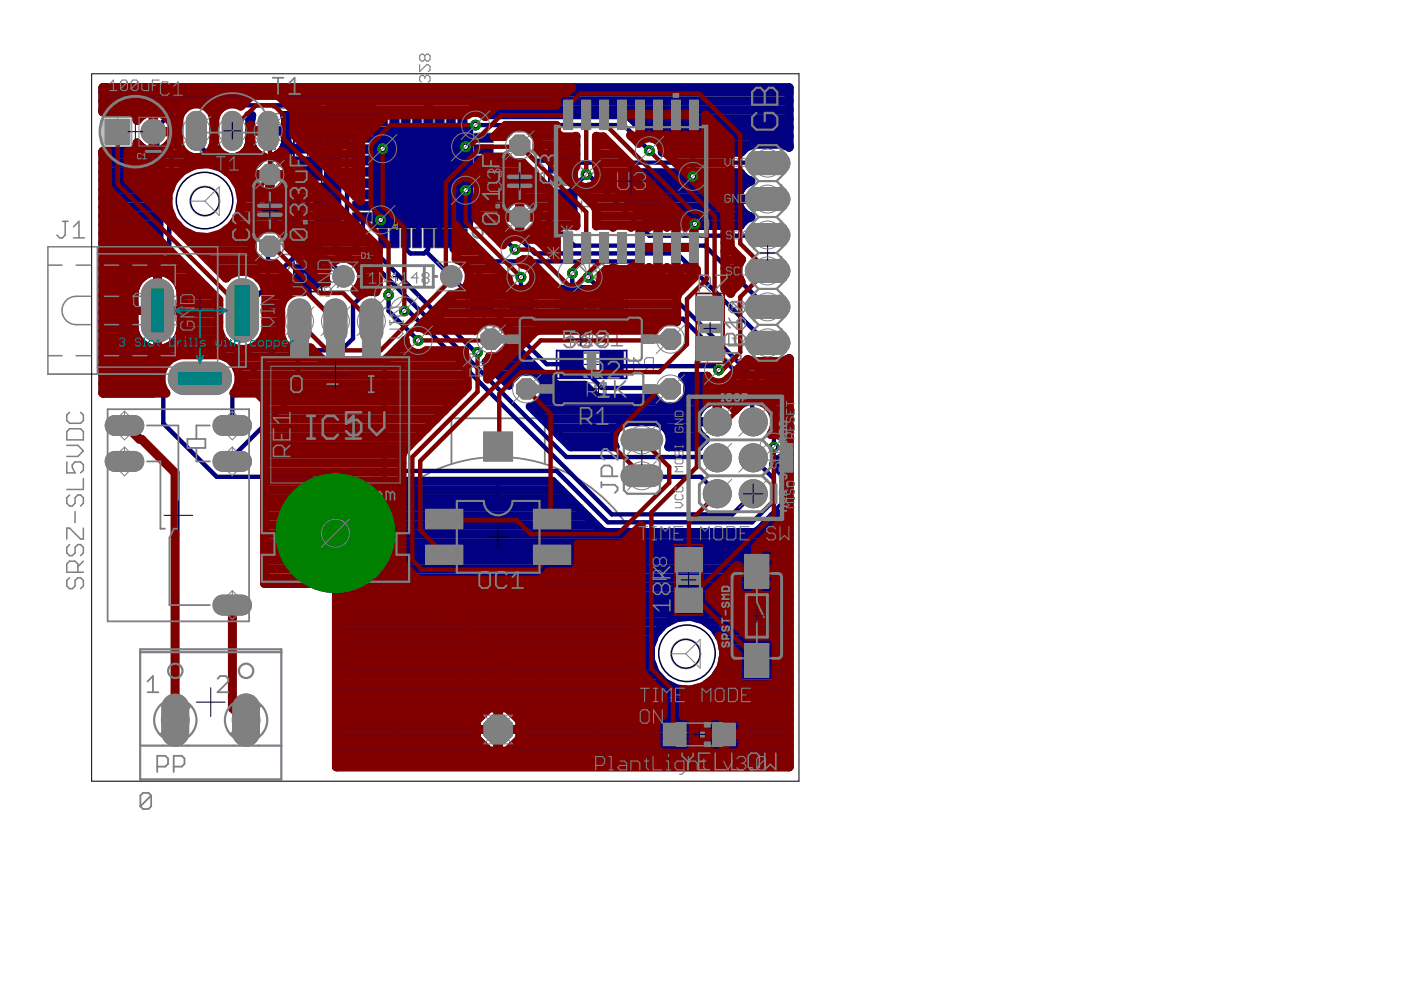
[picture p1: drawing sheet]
<svg xmlns="http://www.w3.org/2000/svg" width="297mm" height="210mm" viewBox="0 0 297 210" stroke-linecap="round" stroke-linejoin="round" font-family="sans-serif">
<g fill="none" stroke="#000" stroke-width=".21">
<path d="M63.4 31.5h3.7M65.2 29.7v3.6M86.6 37.6h6.1M89.6 34.6v6.1M117.8 38.4h3.1M119.3 36.9v3M63.4 54.4h3.7M65.2 52.6v3.6M104.8 63.5h3.1M106.4 62v3.1M123.9 77.3h3.1M123.9 63.5h3.1"/>
<path d="M125.4 62v3.1M125.4 75.7v3.1M102.6 136.7h6.1M105.6 133.6v6.1"/>
</g>
<g fill="none" stroke="#808080" stroke-width=".32">
<path d="M57.8 27.6v2.3M57.8 31.1h.6v.6h-.6zM57.8 28.8h3.5l-1.2 1.1M59.5 21.8v1.1M60.1 24.1h-2.3v1.7l.6 .6h1.7M60.7 32.9l.6 .5v1.2l-.6 .6h-2.3M60.7 32.9h-2.3l-.6 .5v1.2l.6 .6M60.7 32.9l-2.3 2.3M61.3 20.6v2.3h-3.5M62.9 28.7v5.7M67.6 28.7v5.7M69.8 32.9l-.6 .5v1.2l.6 .6h2.3l.6-.6v-1.2l-.6-.5"/>
<path d="M71 29.4v2.3l1.7-1.8h-3.5M111.9 39.1l1.1 1.2M115.4 35.6v2.4h-1.8l.6-1.2v-.6l-.6-.6h-1.1l-.6 .6v1.2l.6 .6M123.3 38h3.5M123.3 35.6l1.8 1.8M125.1 39.7l-.6-.6h-.6l-.6 .6v1.2l.6 .5h.6l.6-.5M125.1 39.7l.5-.6h.6l.6 .6v1.2l-.6 .5h-.6l-.5-.5M125.1 39.7v1.2M126.8 35.6l-2.3 2.4M58.4 55.1l-.6 .6v1.2l.6 .5h2.3l.6-.5v-1.2l-.6-.6M61.3 51.6v2.4h-1.8l.6-1.2v-.6l-.6-.6h-1.1l-.6 .6v1.2l.6 .6M62.9 51.5v5.8"/>
<path d="M67.6 51.5v5.8M69.2 58.6v2.4M69.2 59.8h3.5l-1.2 1.2M71 52.8v1.2M71.5 55.1h-2.3v1.8l.6 .5h1.7M72.7 51.6v2.4h-3.5M104.2 58.4l.6-.6h1.7v1.2l-.6 .6h-1.1l-.6-.6zM104.2 56.1l1.2 .6 1.1 1.1M108.9 58.4l-1.2 1.2M110 58.4h-1.7l-.6-.6v-1.1l.6-.6h1.7v3.5M111.9 41.4h3.5v-1.7l-.6-.6h-1.2l-.6 .6v1.7M122.6 56.1l2.4 2.3"/>
<path d="M123.3 43.8h3.5l-1.2 1.2M123.3 42.6v2.4M124.4 57.8l-1.8 1.8M125 56.1v3.5M126.7 57.8l-.6-.6v-.5l.6-.6h1.2l.6 .6v.5l-.6 .6M126.7 57.8l-.6 .6v.6l.6 .6h1.2l.6-.6v-.6l-.6-.6M126.7 57.8h1.2M129.6 59.6h2.4M132 57.2l-1.2-1.1v3.5M69.2 62.1h.6v.6h-.6zM72.1 63.9l.6 .6v1.1l-.6 .6h-2.3M72.1 63.9h-2.3l-.6 .6v1.1l.6 .6"/>
<path d="M72.1 63.9l-2.3 2.3M100.7 67.5l2.3 2.3M102.4 69.3l-1.7 1.7M103 67.5v3.5M104.8 69.3l-.6 .5v.6l.6 .6h1.1l.6-.6v-.6l-.6-.5M104.8 69.3l-.6-.6v-.6l.6-.6h1.1l.6 .6v.6l-.6 .6M104.8 69.3h1.1M107.7 71h2.3M110 68.7l-1.1-1.2v3.5M122.6 69.8l2.4 2.3M122.6 69.8v.6l.6 .6h1.2l.6-.6M123.2 69.3h.6"/>
<path d="M123.2 69.3l-.6 .5M124.4 71.5l-1.8 1.8M125 69.8v3.5M125 68.1l-.6-.6h-1.2l-.6 .6v.6l.6 .6M126.7 71.5l-.6 .6v.6l.6 .6h1.2l.6-.6v-.6l-.6-.6M126.7 69.8h1.8M126.7 69.8l-.6 .6v.6l.6 .5M126.7 69.8l-.6-.5v-1.2l.6-.6h1.8v3.5M126.7 71.5h1.2M127.3 69.8l-1.2 1.2M127.9 69.8l.6 .6M128.5 71l-.6 .5"/>
<path d="M129.6 73.3h2.4M132 71l-1.2-1.2v3.5M122.6 83h2.4l-1.8-1.8v3.5M127.3 83.5l-1.2 1.2M128.5 83.5h-1.8l-.6-.5v-1.2l.6-.6h1.8v3.5"/>
</g>
<g fill="none" stroke="#808080" stroke-width=".23">
<path d="M89 13.7v1.5l1.4-1.5h.4l.4 .4v.7l-.4 .4M90.1 11.9v.7M90.1 16.3v.4M90.1 11.9l.3-.4h.4l.4 .4v.7l-.4 .4h-.4l-.3-.4M90.1 16.3l.3-.3h.4l.4 .3v.8l-.4 .3M90.1 11.9l-.4-.4h-.4l-.3 .4v.7l.3 .4h.4l.4-.4M90.1 16.3l-.4-.3h-.4l-.3 .3v.8l.3 .3M91.2 18.2l-2.2 1.5M89 23.1l.3-.4h.4l.4 .4v1.1h-.8l-.3-.4zM89 36.2v1.5h2.2v-1.5M89 38.4h2.2l-.8 .8 .8 .7h-2.2M89 25v1.4"/>
<path d="M89 31.7h1.4l.8 .7-.8 .7h-1.4M89 25.7h2.2l-.8 .7M90.1 20.8v.8M90.1 29.8v.7M90.1 31.7v1.4M90.1 36.9v.8M90.1 20.8l.3-.3h.4l.4 .3v.8l-.4 .3h-.4l-.3-.3M90.1 29.8l.3-.4h.4l.4 .4v.7l-.4 .4h-.4l-.3-.4M90.1 20.8l-.4-.3h-.4l-.3 .3v.8l.3 .3h.4l.4-.3M90.1 29.8l-.4-.4h-.4l-.3 .4v.7l.3 .4h.4l.4-.4M90.8 33.9l.4 .4v.7l-.4 .4h-1.5l-.3-.4v-.7l.3-.4h.8v.8M91.2 27.2l-2.2 1.5"/>
<path d="M91.2 22.7l-.4 .7-.7 .8M89 42.9h1.4l.8 .7-.8 .8h-1.4M89 41.4h2.2M90.1 42.9v1.5M91.2 40.7v1.4M106.1 40.3v1.5l1.1-1.2h-2.2M107.2 42.5h-1.9l-.3 .4v.7l.3 .4h1.9"/>
</g>
<path d="M116.9 35.5v5.8M121.8 35.5v5.8M103.5 61.1h5.8M103.5 66h5.8M122.5 74.8h5.8M122.5 79.7h5.8M122.5 61.1h5.8M122.5 66h5.8" fill="none" stroke="#808080" stroke-width=".47"/>
<g fill="#808080" stroke="#808080" stroke-width=".21">
<path d="M120.4 74.6h2.2v5.3h-2.2z"/>
<path d="M128.3 74.6h2.2v5.3h-2.2z"/>
<path d="M116.7 33.3h5.3v2.2h-5.3z"/>
<path d="M116.7 41.3h5.3v2.2h-5.3z"/>
<path d="M120.4 60.9h2.2v5.3h-2.2z"/>
<path d="M128.3 60.9h2.2v5.3h-2.2z"/>
<path d="M109.2 60.9h2.2v5.3h-2.2z"/>
<path d="M101.3 60.9h2.2v5.3h-2.2z"/>
<path d="M97.3 48.3h1.4v3h-1.4z"/>
<path d="M94.9 48.3h1.4v3h-1.4z"/>
<path d="M92.5 48.3h1.4v3h-1.4z"/>
<path d="M90.1 48.3h1.4v3h-1.4z"/>
<path d="M87.7 48.3h1.4v3h-1.4z"/>
<path d="M85.3 48.3h1.4v3h-1.4z"/>
<path d="M83 48.3h1.3v3h-1.3z"/>
<path d="M80.5 48.3h1.4v3h-1.4z"/>
<path d="M76 45.4h3v1.3h-3z"/>
<path d="M76 43h3v1.3h-3z"/>
<path d="M76 40.6h3v1.3h-3z"/>
<path d="M76 38.2h3v1.3h-3z"/>
<path d="M76 35.8h3v1.3h-3z"/>
<path d="M76 33.4h3v1.3h-3z"/>
<path d="M76 31h3v1.3h-3z"/>
<path d="M76 28.6h3v1.3h-3z"/>
<path d="M80.5 24h1.4v3h-1.4z"/>
<path d="M83 24h1.3v3h-1.3z"/>
<path d="M85.3 24h1.4v3h-1.4z"/>
<path d="M87.7 24h1.4v3h-1.4z"/>
<path d="M90.1 24h1.4v3h-1.4z"/>
<path d="M92.5 24h1.4v3h-1.4z"/>
<path d="M94.9 24h1.4v3h-1.4z"/>
<path d="M97.3 24h1.4v3h-1.4z"/>
<path d="M100.3 28.6h3v1.3h-3z"/>
<path d="M100.3 31h3v1.3h-3z"/>
<path d="M100.3 33.4h3v1.3h-3z"/>
<path d="M100.3 35.8h3v1.3h-3z"/>
<path d="M100.3 38.2h3v1.3h-3z"/>
<path d="M100.3 40.6h3v1.3h-3z"/>
<path d="M100.3 43h3v1.3h-3z"/>
<path d="M100.3 45.4h3v1.3h-3z"/>
<path d="M62.7 34.4h5.1v2.2h-5.1z"/>
<path d="M62.7 26.4h5.1v2.3h-5.1z"/>
<path d="M62.7 49.3h5.1v2.2h-5.1z"/>
<path d="M62.7 57.3h5.1v2.2h-5.1z"/>
<path d="M124.5 75.2h1.8v4.2h-1.8z"/>
<path d="M117.2 37.5h4.2v1.8h-4.2z"/>
<path d="M124.5 61.4h1.8v4.2h-1.8z"/>
<path d="M105.5 61.4h1.8v4.2h-1.8z"/>
<path d="M64 30.9h2.4v1.2h-2.4z"/>
<path d="M64 53.8h2.4v1.2h-2.4z"/>
<path d="M127.3 74.5h4.8v5.5h-4.8z"/>
<path d="M118.8 74.5h4.7v5.5h-4.7z"/>
<path d="M116.6 40.3h5.4v4.8h-5.4z"/>
<path d="M116.6 31.7h5.4v4.8h-5.4z"/>
<path d="M127.3 60.8h4.8v5.5h-4.8z"/>
<path d="M118.8 60.8h4.7v5.5h-4.7z"/>
<path d="M99.7 60.8h4.8v5.5h-4.8z"/>
<path d="M108.2 60.8h4.8v5.5h-4.8z"/>
<path d="M97.2 48.6h1.7v3.8h-1.7z"/>
<path d="M94.8 48.6h1.7v3.8h-1.7z"/>
<path d="M92.4 48.6h1.7v3.8h-1.7z"/>
<path d="M90 48.6h1.7v3.8h-1.7z"/>
<path d="M87.6 48.6h1.7v3.8h-1.7z"/>
<path d="M85.2 48.6h1.7v3.8h-1.7z"/>
<path d="M82.8 48.6h1.7v3.8h-1.7z"/>
<path d="M80.4 48.6h1.7v3.8h-1.7z"/>
<path d="M74.8 45.2h3.9v1.7h-3.9z"/>
<path d="M74.8 42.8h3.9v1.7h-3.9z"/>
<path d="M74.8 40.4h3.9v1.7h-3.9z"/>
<path d="M74.8 38h3.9v1.7h-3.9z"/>
<path d="M74.8 35.6h3.9v1.7h-3.9z"/>
<path d="M74.8 33.2h3.9v1.7h-3.9z"/>
<path d="M74.8 30.8h3.9v1.7h-3.9z"/>
<path d="M74.8 28.4h3.9v1.7h-3.9z"/>
<path d="M80.4 22.9h1.7v3.8h-1.7z"/>
<path d="M82.8 22.9h1.7v3.8h-1.7z"/>
<path d="M85.2 22.9h1.7v3.8h-1.7z"/>
<path d="M87.6 22.9h1.7v3.8h-1.7z"/>
<path d="M90 22.9h1.7v3.8h-1.7z"/>
<path d="M92.4 22.9h1.7v3.8h-1.7z"/>
<path d="M94.8 22.9h1.7v3.8h-1.7z"/>
<path d="M97.2 22.9h1.7v3.8h-1.7z"/>
<path d="M100.6 28.4h3.8v1.7h-3.8z"/>
<path d="M100.6 30.8h3.8v1.7h-3.8z"/>
<path d="M100.6 33.2h3.8v1.7h-3.8z"/>
<path d="M100.6 35.6h3.8v1.7h-3.8z"/>
<path d="M100.6 38h3.8v1.7h-3.8z"/>
<path d="M100.6 40.4h3.8v1.7h-3.8z"/>
<path d="M100.6 42.8h3.8v1.7h-3.8z"/>
<path d="M100.6 45.2h3.8v1.7h-3.8z"/>
<path d="M62.5 33.4h5.4v4.7h-5.4z"/>
<path d="M62.5 25h5.4v4.7h-5.4z"/>
<path d="M62.5 47.8h5.4v4.8h-5.4z"/>
<path d="M62.5 56.2h5.4v4.8h-5.4z"/>
<path d="M35 148.1a2.84 2.84 0 0 1 3-.8 2.84 2.84 0 0 1 2 2.5v5.8a2.85 2.85 0 0 1-2.8 2.6 2.85 2.85 0 0 1-2.9-2.6v-5.8l.2-.9z"/>
<path d="M50 148.1a2.84 2.84 0 0 1 3.1-.8 2.84 2.84 0 0 1 1.9 2.5v5.8a2.85 2.85 0 0 1-2.8 2.6 2.85 2.85 0 0 1-2.9-2.6v-5.8l.3-.9z"/>
<path d="M22.8 88.9a2.14 2.14 0 0 1 1.4-.8h4.4a2.13 2.13 0 0 1 1.9 2.1 2.13 2.13 0 0 1-1.9 2.1h-4.4a2.13 2.13 0 0 1-1.4-3.4z"/>
<path d="M22.8 96.5a2.14 2.14 0 0 1 1.4-.8h4.4a2.13 2.13 0 0 1 1.9 2.1 2.13 2.13 0 0 1-1.9 2.1h-4.4a2.13 2.13 0 0 1-1.4-3.4z"/>
<path d="M45.6 126.9a2.14 2.14 0 0 1 1.5-.7h4.3a2.13 2.13 0 0 1 1.9 2.1 2.13 2.13 0 0 1-1.9 2.1h-4.3a2.13 2.13 0 0 1-1.5-3.5z"/>
<path d="M45.6 88.9a2.14 2.14 0 0 1 1.5-.8h4.3a2.13 2.13 0 0 1 1.9 2.1 2.13 2.13 0 0 1-1.9 2.1h-4.3a2.13 2.13 0 0 1-1.5-3.4z"/>
<path d="M45.6 96.5a2.14 2.14 0 0 1 1.5-.8h4.3a2.13 2.13 0 0 1 1.9 2.1 2.13 2.13 0 0 1-1.9 2.1h-4.3a2.13 2.13 0 0 1-1.5-3.4z"/>
<path d="M76.9 64.2a2.45 2.45 0 0 1 2.6-.7 2.45 2.45 0 0 1 1.7 2.1v5a2.44 2.44 0 0 1-2.5 2.2 2.44 2.44 0 0 1-2.4-2.2v-5l.2-.7z"/>
<path d="M69.3 64.2a2.45 2.45 0 0 1 2.6-.7 2.45 2.45 0 0 1 1.7 2.1v5a2.44 2.44 0 0 1-2.5 2.2 2.44 2.44 0 0 1-2.4-2.2v-5l.2-.7z"/>
<path d="M61.6 64.2a2.45 2.45 0 0 1 2.7-.7 2.45 2.45 0 0 1 1.6 2.1v5a2.44 2.44 0 0 1-2.4 2.2 2.44 2.44 0 0 1-2.4-2.2v-5l.1-.7z"/>
<path d="M22.3 25.3h5.2v5.2h-5.2z"/>
<path d="M158.6 71.1l.9-.7 .8-.1h4.9a2.44 2.44 0 0 1 2.3 2.4 2.44 2.44 0 0 1-2.3 2.4h-4.9a2.44 2.44 0 0 1-2.1-1.5 2.44 2.44 0 0 1 .4-2.5z"/>
<path d="M158.6 63.5l.9-.7 .8-.2h4.9a2.44 2.44 0 0 1 2.3 2.5 2.44 2.44 0 0 1-2.3 2.4h-4.9a2.44 2.44 0 0 1-2.1-1.5 2.44 2.44 0 0 1 .4-2.5z"/>
<path d="M158.6 55.9l.9-.7 .8-.2h4.9a2.44 2.44 0 0 1 2.3 2.4 2.44 2.44 0 0 1-2.3 2.5h-4.9a2.44 2.44 0 0 1-2.1-1.5 2.44 2.44 0 0 1 .4-2.5z"/>
<path d="M158.6 48.2l.9-.6 .8-.2h4.9a2.44 2.44 0 0 1 2.3 2.4 2.44 2.44 0 0 1-2.3 2.5h-4.9a2.44 2.44 0 0 1-2.1-1.5 2.44 2.44 0 0 1 .4-2.6z"/>
<path d="M158.6 40.6l.9-.7 .8-.1h4.9a2.44 2.44 0 0 1 2.3 2.4 2.44 2.44 0 0 1-2.3 2.4h-4.9a2.44 2.44 0 0 1-2.1-1.5 2.44 2.44 0 0 1 .4-2.5z"/>
<path d="M158.6 33l.9-.7 .8-.1h4.9a2.44 2.44 0 0 1 2.3 2.4 2.44 2.44 0 0 1-2.3 2.4h-4.9a2.44 2.44 0 0 1-2.1-1.5 2.44 2.44 0 0 1 .4-2.5z"/>
<path d="M127.1 74.4h5.1v5.7h-5.1z"/>
<path d="M118.6 74.4h5.1v5.7h-5.1z"/>
<path d="M116.5 40.1h5.7v5.1h-5.7z"/>
<path d="M116.5 31.6h5.7v5.1h-5.7z"/>
<path d="M102.6 91.6h6.1v6.1h-6.1z"/>
<path d="M127.1 60.7h5.1v5.7h-5.1z"/>
<path d="M118.6 60.7h5.1v5.7h-5.1z"/>
<path d="M99.5 60.7h5.2v5.7h-5.2z"/>
<path d="M108.1 60.7h5.1v5.7h-5.1z"/>
<path d="M97 48.5h2v4.1h-2z"/>
<path d="M94.6 48.5h2v4.1h-2z"/>
<path d="M92.2 48.5h2v4.1h-2z"/>
<path d="M89.8 48.5h2v4.1h-2z"/>
<path d="M87.4 48.5h2v4.1h-2z"/>
<path d="M85 48.5h2v4.1h-2z"/>
<path d="M82.6 48.5h2v4.1h-2z"/>
<path d="M80.2 48.5h2v4.1h-2z"/>
<path d="M74.7 45h4.1v2h-4.1z"/>
<path d="M74.7 42.7h4.1v1.9h-4.1z"/>
<path d="M74.7 40.2h4.1v2h-4.1z"/>
<path d="M74.7 37.8h4.1v2h-4.1z"/>
<path d="M74.7 35.5h4.1v1.9h-4.1z"/>
<path d="M74.7 33h4.1v2h-4.1z"/>
<path d="M74.7 30.6h4.1v2h-4.1z"/>
<path d="M74.7 28.2h4.1v2h-4.1z"/>
<path d="M80.2 22.7h2v4.1h-2z"/>
<path d="M82.6 22.7h2v4.1h-2z"/>
<path d="M85 22.7h2v4.1h-2z"/>
<path d="M87.4 22.7h2v4.1h-2z"/>
<path d="M89.8 22.7h2v4.1h-2z"/>
<path d="M92.2 22.7h2v4.1h-2z"/>
<path d="M94.6 22.7h2v4.1h-2z"/>
<path d="M97 22.7h2v4.1h-2z"/>
<path d="M100.4 28.2h4.1v2h-4.1z"/>
<path d="M100.4 30.6h4.1v2h-4.1z"/>
<path d="M100.4 33h4.1v2h-4.1z"/>
<path d="M100.4 35.5h4.1v1.9h-4.1z"/>
<path d="M100.4 37.8h4.1v2h-4.1z"/>
<path d="M100.4 40.2h4.1v2h-4.1z"/>
<path d="M100.4 42.7h4.1v1.9h-4.1z"/>
<path d="M100.4 45h4.1v2h-4.1z"/>
<path d="M62.4 33.2h5.7v5.1h-5.7z"/>
<path d="M62.4 24.8h5.7v5.1h-5.7z"/>
<path d="M62.4 47.6h5.7v5.2h-5.7z"/>
<path d="M62.4 56h5.7v5.2h-5.7z"/>
<path d="M40 24.4a2.14 2.14 0 0 1 2.3-.7 2.14 2.14 0 0 1 1.5 1.8v4.4a2.15 2.15 0 0 1-2.2 2 2.15 2.15 0 0 1-2.1-2v-4.4z"/>
<path d="M55.2 24.4a2.14 2.14 0 0 1 2.3-.7 2.14 2.14 0 0 1 1.5 1.8v4.4a2.15 2.15 0 0 1-2.1 2 2.15 2.15 0 0 1-2.2-2v-4.4z"/>
<path d="M47.6 24.4a2.14 2.14 0 0 1 2.3-.7 2.14 2.14 0 0 1 1.5 1.8v4.4a2.15 2.15 0 0 1-2.1 2 2.15 2.15 0 0 1-2.2-2v-4.4z"/>
<path d="M132.5 99.1l.6-.3 .7-.2h4.6a2.29 2.29 0 0 1 2.1 2.3 2.29 2.29 0 0 1-2.1 2.3h-4.6a2.29 2.29 0 0 1-2-1.6 2.29 2.29 0 0 1 .7-2.5z"/>
<path d="M132.5 91.5l.6-.4 .7-.1h4.6a2.29 2.29 0 0 1 2.1 2.3 2.29 2.29 0 0 1-2.1 2.2h-4.6a2.29 2.29 0 0 1-2-1.5 2.29 2.29 0 0 1 .7-2.5z"/>
<path d="M36.5 78l1.1-.9 1.3-.3h7a3.4 3.4 0 0 1 3.2 3.4 3.4 3.4 0 0 1-3.2 3.5h-7a3.4 3.4 0 0 1-3-2.2 3.4 3.4 0 0 1 .6-3.5z"/>
<path d="M30.8 60.3a3.4 3.4 0 0 1 3.7-1 3.4 3.4 0 0 1 2.3 3v7a3.4 3.4 0 0 1-3.4 3.2 3.4 3.4 0 0 1-3.4-3.2v-7l.3-1.3z"/>
<path d="M48.8 60.3a3.4 3.4 0 0 1 3.7-1 3.4 3.4 0 0 1 2.3 3v7a3.4 3.4 0 0 1-3.4 3.2 3.4 3.4 0 0 1-3.4-3.2v-7l.3-1.3z"/>
<circle cx="142.1" cy="82.5" r="2.32"/>
<circle cx="111.6" cy="82.5" r="2.32"/>
<circle cx="57.2" cy="52.2" r="2.32"/>
<circle cx="57.2" cy="37" r="2.32"/>
<circle cx="105.6" cy="154.7" r="3.3"/>
<circle cx="110.2" cy="30.8" r="2.32"/>
<circle cx="110.2" cy="46" r="2.32"/>
<circle cx="142.2" cy="71.9" r="2.32"/>
<circle cx="104.1" cy="71.9" r="2.32"/>
</g>
<g fill="none" stroke="#7f7f7f" stroke-width=".23">
<path d="M59 32.1l-.5 .5v.9l.5 .5h1.9l.4-.5v-.9l-.4-.5M59.9 29.3v1.9l1.4-1.4h-2.8M123.3 38.7l.9 .9M126.1 35.9v1.9h-1.4l.4-1v-.4l-.4-.5h-1l-.4 .5v.9l.4 .5M69.6 53.9l-.4 .5v.9l.4 .5h1.9l.5-.5v-.9l-.5-.5M72 51.1v1.9h-1.4l.5-.9v-.5l-.5-.5h-1l-.4 .5v.9l.4 .5M123.3 40.6h2.8v-1.4l-.5-.5h-.9l-.5 .5v1.4M131.3 59l-.5 .4v.5l.5 .5h.9l.5-.5M131.3 59h.4M132.7 58l-.5-.4h-.9l-.5 .4v.5l.5 .5M134.6 59.4l-1 1M135.5 59.4h-1.4l-.5-.4v-1l.5-.4h1.4v2.8"/>
<path d="M98.8 65.9l1 .5 .9 1M98.8 67.8l.5-.4h1.4v.9l-.5 .5h-.9l-.5-.5zM102.6 67.8l-1 1M103.5 67.8h-1.4l-.5-.4v-1l.5-.5h1.4v2.9M133.9 77.3h1.8l-1.4-1.5v2.9M137.6 77.7l-.9 1M138.5 77.7h-1.4l-.4-.4v-1l.4-.5h1.4v2.9"/>
</g>
<path d="M104 103.9h3.2M105.6 102.3v3.2M104 159.4h3.2" fill="none" stroke="#7f7f7f" stroke-width=".76"/>
<g fill="none" stroke="#7f7f7f" stroke-width=".38">
<path d="M95.7 88.7v9.6M95.9 88.7h19.5M115.5 88.7v9.6M96.5 126.4v3.5l2.3-3.5v3.5M100.6 126.4h1.1l.6 .6v2.3l-.6 .6h-1.1l-.6-.6v-2.3zM105.8 126.4h-2.3v.6l2.3 2.3v.6h-2.3M107 128.1h2.3M107 129.9v-2.3l1.2-1.2 1.1 1.2v2.3M110.6 129.9v-3.5l1.1 1.2 1.1-1.2v3.5M112.7 133.9l-.6-.6h-1.1l-.6 .6v.6l2.3 2.3h-2.3M113.9 133.9l.6-.6h1.2l.5 .6v2.3l-.5 .6h-1.2l-.6-.6v-1.2h1.2M114.1 128.1h2.3"/>
<path d="M114.1 129.9v-2.3l1.1-1.2 1.2 1.2v2.3M119.8 127l-.5-.6h-1.2l-.5 .6v.6l2.2 2.3h-2.2M121.6 128.1l-.5 .6v.6l.5 .6h1.2l.6-.6M121.6 128.1h.6M123.4 127l-.6-.6h-1.2l-.5 .6v.6l.5 .5M124.6 127l.6-.6h1.1l.6 .6v2.3M124.6 127v2.3l.6 .6h1.1l.6-.6M124.6 127l2.3 2.3M130.4 127l-.6-.6h-1.1l-.6 .6v.6l2.3 2.3h-2.3M132.7 128.7l-1.1 1.2M133.9 128.7h-1.7l-.6-.6v-1.1l.6-.6h1.7v3.5M135.1 127l.6-.6h1.1l.6 .6v2.3l-.6 .6h-1.1l-.6-.6"/>
<path d="M98.1 143.4v2.3l1.2 1.1 1.1-1.1v-2.3M102.2 145.1l-.5 .6v.6l.5 .5h1.2l.5-.5M102.2 145.1h.6M103.9 144l-.5-.6h-1.2l-.5 .6v.5l.5 .6M105.1 146.3h.6v.5h-.6zM106.9 144.5h1.1M107.5 144v2.3l-.6 .5M109.2 146.8h1.2M109.8 142.8v.6M110.4 144.5h-.6v2.3M113.9 143.4v3.4h-2.3"/>
<circle cx="105.6" cy="129.9" r="33"/>
</g>
<g fill="none" stroke="#7f7f7f" stroke-width=".47">
<path d="M79.1 27.1h21v20l-1 1.1h-20z"/>
<circle cx="101.3" cy="49.3" r="1.08"/>
</g>
<path d="M164.5 102.8v3.8" fill="none" stroke="#7f7f7f" stroke-width=".61"/>
<g fill="#808080" stroke="#808080" stroke-width=".21">
<circle cx="145.4" cy="138.6" r="3.2"/>
<circle cx="43.4" cy="42.7" r="3.2"/>
<circle cx="72.8" cy="58.6" r="2.27"/>
<circle cx="95.7" cy="58.6" r="2.27"/>
<circle cx="71.1" cy="113.1" r="5.1"/>
<circle cx="32.5" cy="27.9" r="2.62"/>
<circle cx="159.7" cy="104.7" r="2.96"/>
<circle cx="152.1" cy="104.7" r="2.96"/>
<circle cx="159.7" cy="97.1" r="2.96"/>
<circle cx="152.1" cy="97.1" r="2.96"/>
<circle cx="159.7" cy="89.5" r="2.96"/>
<circle cx="152.1" cy="89.5" r="2.96"/>
</g>
<g fill="#000080" stroke="#000080" stroke-width=".21">
<path d="M117.9 80.2h15z"/>
<path d="M132.8 74.3h.1v6z"/>
<path d="M118 74.3l14.9 .1h-14.9z"/>
<path d="M118 74.3v6z"/>
<path d="M116.3 31h.2l-.1 14.9z"/>
<path d="M116.3 45.8l6.1 .1z"/>
<path d="M122.2 31h.2l-.1 14.9z"/>
<path d="M116.3 31h6.1z"/>
<path d="M117.9 66.5h15z"/>
<path d="M132.8 60.5l.1 6.1z"/>
<path d="M117.9 60.6h15z"/>
<path d="M117.9 60.6h.2l-.1 6z"/>
<path d="M98.9 60.6h15z"/>
<path d="M98.9 60.6h.1v6z"/>
<path d="M98.9 66.5h15z"/>
<path d="M113.7 60.6h.2l-.1 6z"/>
<path d="M79.1 27.1h21v21.1h-21z"/>
<path d="M68.1 24.1h.2l-.1 15z"/>
<path d="M62.2 24.1h.2l-.1 15z"/>
<path d="M62.2 38.9l6.1 .1z"/>
<path d="M62.2 24.1l6.1 .1z"/>
<path d="M62.2 47h.2l-.1 14.9z"/>
<path d="M68.1 47h.2l-.1 14.9z"/>
<path d="M62.2 47h6.1z"/>
<path d="M62.2 61.8h6.1z"/>
<path d="M127.3 74.5h4.8v5.5h-4.8z"/>
<path d="M118.8 74.5h4.7v5.5h-4.7z"/>
<path d="M116.6 40.3h5.4v4.8h-5.4z"/>
<path d="M116.6 31.7h5.4v4.8h-5.4z"/>
<path d="M127.3 60.8h4.8v5.5h-4.8z"/>
<path d="M118.8 60.8h4.7v5.5h-4.7z"/>
<path d="M99.7 60.8h4.8v5.5h-4.8z"/>
<path d="M108.2 60.8h4.8v5.5h-4.8z"/>
<path d="M97.2 48.6h1.7v3.8h-1.7z"/>
<path d="M94.8 48.6h1.7v3.8h-1.7z"/>
<path d="M92.4 48.6h1.7v3.8h-1.7z"/>
<path d="M90 48.6h1.7v3.8h-1.7z"/>
<path d="M87.6 48.6h1.7v3.8h-1.7z"/>
<path d="M85.2 48.6h1.7v3.8h-1.7z"/>
<path d="M82.8 48.6h1.7v3.8h-1.7z"/>
<path d="M80.4 48.6h1.7v3.8h-1.7z"/>
<path d="M74.8 45.2h3.9v1.7h-3.9z"/>
<path d="M74.8 42.8h3.9v1.7h-3.9z"/>
<path d="M74.8 40.4h3.9v1.7h-3.9z"/>
<path d="M74.8 38h3.9v1.7h-3.9z"/>
<path d="M74.8 35.6h3.9v1.7h-3.9z"/>
<path d="M74.8 33.2h3.9v1.7h-3.9z"/>
<path d="M74.8 30.8h3.9v1.7h-3.9z"/>
<path d="M74.8 28.4h3.9v1.7h-3.9z"/>
<path d="M80.4 22.9h1.7v3.8h-1.7z"/>
<path d="M82.8 22.9h1.7v3.8h-1.7z"/>
<path d="M85.2 22.9h1.7v3.8h-1.7z"/>
<path d="M87.6 22.9h1.7v3.8h-1.7z"/>
<path d="M90 22.9h1.7v3.8h-1.7z"/>
<path d="M92.4 22.9h1.7v3.8h-1.7z"/>
<path d="M94.8 22.9h1.7v3.8h-1.7z"/>
<path d="M97.2 22.9h1.7v3.8h-1.7z"/>
<path d="M100.6 28.4h3.8v1.7h-3.8z"/>
<path d="M100.6 30.8h3.8v1.7h-3.8z"/>
<path d="M100.6 33.2h3.8v1.7h-3.8z"/>
<path d="M100.6 35.6h3.8v1.7h-3.8z"/>
<path d="M100.6 38h3.8v1.7h-3.8z"/>
<path d="M100.6 40.4h3.8v1.7h-3.8z"/>
<path d="M100.6 42.8h3.8v1.7h-3.8z"/>
<path d="M100.6 45.2h3.8v1.7h-3.8z"/>
<path d="M62.5 33.4h5.4v4.7h-5.4z"/>
<path d="M62.5 25h5.4v4.7h-5.4z"/>
<path d="M62.5 47.8h5.4v4.8h-5.4z"/>
<path d="M62.5 56.2h5.4v4.8h-5.4z"/>
</g>
<circle cx="71.1" cy="113.1" r="12.6" fill="#000080" stroke="#000080" stroke-width=".21"/>
<g fill="none" stroke="#000080" stroke-width=".93">
<path d="M41.6 27.7l.1 2.6 19.3 19.3v3.3l1.3 1.3v.4M65.2 27.3h-8l-.3 .4M65.2 35.8v14.4l.4 .2h3.8l7.1 7.1v5.5l-1.7 1.6v7.2l-2.5 2.5h-9.2M76.8 31.6l-.3 .4h-2.5l-.4 .4v18l46.5 46.5h31.8l.2 .2M76.8 29.2l.1 .2h2.1l2.1 2.1M81.2 24.8l-.1-.4h-11.7l-2.1-2.1h-26.8l-4.2 4.2v13.8l-.4 .5v17.6l2.1 2.1v14.2l-3.4 3.4v11.7l11.3 11.3h19.7l1.3-1.3h51.1l10.9 10.9h30.6l4.6-4.6v-4.6l-4.4-4.4M83.6 24.8v21l2.1 2.1v2.5l.3 .1 .1 .3v2.1l.9 .8h2.9l.4-.4M98.7 31.1v3.8l1.3 1.3h2.5v.2M100.8 26.5h31.4l5.5 5.5M102.5 34l8.4 .1 8.4 8.6v-.7l5-5h.4l13 13h24.7l.4-.2M102.5 38.8v.3h-2.5l-1.3 1.2M110.2 30.8l3.2 3.3h5.9l.4 .4 43.1 .1"/>
<path d="M146.9 37.4l5 5h10.5l.4-.2M57.2 52.2l-.4 .3v8l-5.4 5.3M62.3 54.6l-2.5 2.5v15.5l-10.5 10.5v7.1M62.3 54.6h6.7l3.7 3.8 .1 .2M65.2 58.6l.4 .2v3.7l5.5 5.6M76.8 46l.1 .2v4.6l23.9 23.9h.4M76.8 41.2h2.2l1.7 1.7v3.7M88.4 50.5l.3-.1v-2.5l.8-.8h2.5l1.3 1.2-.1 2.2M90.3 53.3l10.1 10.1h1.7l13.8 13.8h5l.3 .1 .1 .3h1.7l4.6 4.7h14.3l.2 .2M90.8 47.1v-24.8l-1.7-1.6h-49.5l-7.1 7.2v.3l.9 .8v36.8M90.8 50.5v2.4l-.5 .4M95.6 50.5l.2 .3v2.1l2.5 2.5h36.9l28.9 28.9v10.5"/>
<path d="M102.5 43.6l2.5 .1 1.7 1.7v1.7l6.7 6.6h30.2l18.8 18.9 .4 .1M102.5 41.2h8.4l10.9 10.9h27.6l13 13h.4M102.5 46v.2l6.7 6.7M110.4 58.8v4.6l4.2 4.2h30.2l14.7 14.7v7.1l.2 .1M121.3 57.9v5.5l-.1 .1M124.7 58.8l4.6 4.6 .4 .1M152.4 42.4l-5.1 5.1M63.5 68.1l-.4 .3v14.7l-13.8 13.8v.9M82.4 62.5v3.4l6.3 6.3M85.7 65.9h.9l43.1 43.2h25.6l4.4-4.4M129.7 77.3v.3h21.8l.9 .9M136.1 100.9l.3 .2h12.2l3.5 3.6"/>
</g>
<g fill="none" stroke="#000080" stroke-width="1.9">
<path d="M21.8 18.6h145.5v12.6l-1.5-.6h-6.1l-1.5 .6-1.1 1.1h-16.7a2.68 2.68 0 0 0-2.4-3.1l-4.5-4.5-.8-.4h-30.2l-1.1-.5h-.8v-1.7l-1-1h-19.9l-1 1.1h-8.4l-1.8-1.7-.8-.3h-27.7l-.7 .3-4.2 4.1a4.2 4.2 0 0 0-6 .9v-.8l-1-1h-6.3zM21.8 19.5h145.5M21.8 32.1h6.3l1-1v-.8a4.2 4.2 0 0 0 5 1.5v7.6l-.4 .9v17.3a5 5 0 0 0-5.3 4.6v7.2a5 5 0 0 0 7.4 4.1v.3l-3 3-.4 .8v5.8h-10.6zM21.8 38.3h12.3M21.8 36.4h12.3M21.8 34.5h12.3M21.8 32.7h12.3M21.8 23.3h14.6M21.8 21.4h16.5M29.1 30.8h.3M29.1 25.2h.3M32.5 23.7v8.4"/>
<path d="M32.5 27.9h.1M32.5 25.2h.1M32.5 30.8h.1M32.5 28.9h.1M32.5 27v.1M49 34.5h5.4M50.9 36.4h2.6M51.5 32.7h3.1M52.7 24.5h.7l-.2 1v4.5a3.6 3.6 0 0 0 2.7 3.3h-.2l-2.2 2.2v3l2.2 2.2h3l2.1-2.1v.3l1 1h1.2v6.2h-1.2l-.6 .6-13.7-13.7a3.7 3.7 0 0 0 5.4-2.5v-5.5zM52.8 38.3h.7M52.8 30.8h.5M52.9 28.9h.3"/>
<path d="M52.9 27h.3M52.9 25.2h.3M53.2 27.7h7.4M53.5 37h3.7M56.9 27.7h.1M57.2 37h.1M57.2 37v3.7M57.2 38.3h.1M59.1 32.7h1.7M60 34.5h.8M60.4 30.8h.8M60.5 25.2h.3"/>
<path d="M60.6 28.9h.2M60.6 27h.2M60.8 32.6l1-1h6.8l1.1 1M61.2 30.8l.7 .5 .4 .2h2.7v-4.4h-4.2l.1-2.6h-.6l.3 1v4.5a3.6 3.6 0 0 1-2.8 3.3h.9l2.1 2.1v-2.8M61.2 30.8l-.4-.8v-2.4h8.9v2.4l-.4 .8M65 30.8h.5M65 28.9h.5M69.3 30.8l-.7 .5-.4 .2h-2.7v-4.4h4.2v-.5h9l-4.6 .1-1 1v2.3l-.3 .1-1.1 1.1-.3 .7v17.4l-.8-.7-.9-.4v-1.1l-1.1-1h-1.2v-6.2h1.2l1.1-1v-6.3M69.3 30.8h2.8M69.5 21.4h9.9M69.7 38.3h1.7M69.7 36.4h1.7"/>
<path d="M69.7 34.5h1.7M69.7 32.7h1.7M69.7 28.9h3.4M69.7 27h4.1M90.8 21.1v.9M90.8 22h.1M90.8 21.4h.1M99.8 21.4h67.5M100.6 23.3h66.7M127.4 36.6h29.6l1.2 1.4 1 .4a4 4 0 0 0-2.7 3.8 4 4 0 0 0 2.7 3.8l-1 .4-1.2 1.4h-18.4zM129.1 38.3h29.8M134 25.2h33.3"/>
<path d="M135.8 27h31.5M137.7 28.9h29.6M140.2 30.8h19M166.3 30.8h1M21.8 58.9h8.2M21.8 57h11.9M21.8 55.1h11.9M21.8 53.3h11.9M21.8 51.4h11.9M21.8 49.5h11.9M21.8 47.6h11.9M21.8 45.8h11.9"/>
<path d="M21.8 43.9h11.9M21.8 42h11.9M21.8 40.2h12M33.4 57.6v16.5M33.4 58.9h.1M54.7 40.2h.4M56.5 42h6.5M57.2 40.2h.1M58.4 43.9h4.6M59.3 40.2h3.7M60.3 45.8h2.7M65.5 58.4h3.5v.4h-3.5z"/>
<path d="M67.4 45.8h4M67.4 43.9h4M67.4 42h4M67.4 40.2h4M69.7 47.6h1.7M130.9 40.2h26.1M132.8 42h23.7M134.7 43.9h22.1M136.5 45.8h22.1M138.4 47.6h18.6M156.5 42.2h6.3M21.8 79.5h10.6"/>
<path d="M21.8 77.6h10.6M21.8 75.7h12.1M21.8 73.9h10.1M21.8 72h7.5M21.8 70.1h6.7M21.8 68.2h6.6M21.8 66.4h6.6M21.8 64.5h6.6M21.8 62.6h6.6M21.8 60.7h6.9M28.4 65.8h5M33.4 73.9h.1"/>
<path d="M33.4 72h.1M33.4 70.1h.1M33.4 68.2v.1M33.4 66.4h.1M33.4 64.5h.1M33.4 62.6h.1M33.4 60.7v.1M34.9 73.9h.9M103.8 75.7h7.5M103.8 75.6h1.8l2.2-2.2v-1.2l6.9 6.9 .8 .3h1.6v1.3l.9 1h6l2.4 2.4 .8 .3h11.6l1.8 1.8h3l2.2-2.2v-3.1l-1.1-1.1h5.2a2.68 2.68 0 0 0 4.5 .5l2.9 2.8v2.4l-1.4 1.4a4.5 4.5 0 0 0-7-.7 4.5 4.5 0 0 0 .6 7l-1.4 1.5h-6.3a3.8 3.8 0 0 0-2.8-5.3h-5.8a3.8 3.8 0 0 0-2.8 5.3h-9.4l-8.6-8.5h.8l2.1-2.2v-3.1l-2.1-2.1h-3.1l-2.2 2.1v.8l-4.9-4.9 .6-.5zM103.9 77.6h9.3M105.7 79.5h3.7"/>
<path d="M107.4 73.9h2.1M113.9 79.5h3.2M160.4 77.6h6.9M162.3 79.5h5M21.8 83.2h10.6M21.8 81.3h10.6M107.6 81.3h.3M113.2 87h35.1M114.2 85.1h25.3M115.1 88.8h32.5M115.3 83.2h10.2M115.3 81.3h2.4"/>
<path d="M117 90.7h14.1M118.8 92.6h11.3M120.7 94.5h9.6M141.1 90.7h6.6M141.9 94.5h6.4M142.1 92.6h6.7M144.7 85.1h6.1M145.8 83.2h11.5M145.8 81.3h9.7M147.6 89.5h4.5M152.1 84.9v4.6M152.1 89.5h.1"/>
<path d="M152.1 88.8v.1M152.1 87h.1M152.1 85.1h.1M153.4 85.1h3.9M164.1 98.2h3.2M164.2 81.3h3.1M166 83.2h1.3M166.3 92.6h1M166.3 90.7h1M166.3 88.8h1M166.3 87h1M166.3 85.1h1"/>
<path d="M166.4 96.3h.9M166.8 94.5h.5M79 102h38.1l10.6 10.6 .8 .3h31.4l.8-.3 5.2-5.2 .4-.8v-5.5l-.4-.8-1.9-1.9 .2-.8a2.72 2.72 0 0 0 2.4-1.6 2.72 2.72 0 0 0-.3-2.9v-9.2l-.4-.8-6.5-6.5 .3 .1h6.1l1.5-.6v86.5h-96v-36a13.5 13.5 0 0 0 12.9-9.5 13.5 13.5 0 0 0-5.2-15.1zM81 103.8h37.9M82.5 105.7h38.3M83.4 118.8h83.9M83.6 107.6h39.1M84.1 116.9h83.2M84.2 109.5h40.3M84.6 115.1h82.7M84.6 113.2h82.7M84.6 111.3h41.8"/>
<path d="M162 111.3h5.3M163.8 109.5h3.5M165.7 107.6h1.6M165.7 100.1h1.6M166.3 105.7h1M166.3 103.8h1M166.3 102h1M71.3 139.4h66.6M71.3 137.5h66.6M71.3 135.7h67.2M71.3 133.8h68.2M71.3 131.9h70.3"/>
<path d="M71.3 130h96M71.3 128.2h96M74 126.3h93.3M78.5 124.4h88.8M80.8 122.6h86.5M82.3 120.7h85M139 134.4h.1M139 134.4l-1.1 2.7v2.9l1.1 2.7M140.9 132.2v.1M140.9 132.2l-1.9 2.2M143.5 131h.1M143.5 131l-2.6 1.2"/>
<path d="M146.4 130.7l2.8 .8M146.4 130.7h.1M146.4 130.7l-2.9 .3M149.2 131.5l2.3 1.7M149.2 131.5h.1M149.7 131.9h17.6M151.5 133.2h.1M151.5 133.2l1.5 2.5 .5 2.8M151.8 133.8h15.5M153 135.7h14.3M153.3 137.5h14M153.4 139.4h13.9"/>
<path d="M153.5 138.5l-.5 2.9M153.5 138.5h.1M71.3 158.1h31.3M71.3 156.3h29.7M71.3 154.4h29.7M71.3 152.5h30M71.3 150.6h31.8M71.3 148.8h96M71.3 146.9h96M71.3 145h70.1M71.3 143.2h68.1M71.3 141.3h67.1"/>
<path d="M101 154.7h9.2M105.6 150.1v9.2M105.6 154.7h.1M105.6 158.1v.1M105.6 156.3h.1M105.6 154.4h.1M105.6 152.5h.1M105.6 150.6v.1M108.1 150.6h59.2M108.7 158.1h58.6M110 152.5h57.3M110.2 156.3h57.1"/>
<path d="M110.2 154.4h57.1M139 142.7h.1M139 142.7l1.9 2.1M140.9 144.8h.1M140.9 144.8l2.6 1.3M143.5 146.1h.1M143.5 146.1l2.9 .2M146.4 146.3v.1M149.2 145.6l-2.8 .7M149.2 145.6h.1M149.8 145h17.5M151.5 143.8l-2.3 1.8"/>
<path d="M151.5 143.8h.1M151.9 143.2h15.4M153 141.4l-1.5 2.4M153 141.4h.1M153 141.3h14.3M71.3 161.9h96M71.3 160h96"/>
<circle cx="105.6" cy="154.7" r="5"/>
</g>
<circle cx="72.8" cy="58.6" r="2.12" fill="#008000" stroke="#008000" stroke-width=".21"/>
<circle cx="72.8" cy="58.6" r="1.35" fill="#fff" stroke="#000" stroke-width=".21"/>
<circle cx="95.7" cy="58.6" r="2.12" fill="#008000" stroke="#008000" stroke-width=".21"/>
<circle cx="95.7" cy="58.6" r="1.35" fill="#fff" stroke="#000" stroke-width=".21"/>
<circle cx="142.1" cy="82.5" r="2.15" fill="#008000" stroke="#008000" stroke-width=".21"/>
<circle cx="142.1" cy="82.5" r="1.23" fill="#fff" stroke="#000" stroke-width=".21"/>
<circle cx="111.6" cy="82.5" r="2.15" fill="#008000" stroke="#008000" stroke-width=".21"/>
<circle cx="111.6" cy="82.5" r="1.23" fill="#fff" stroke="#000" stroke-width=".21"/>
<path d="M37.2 150v5.4" fill="none" stroke="#008000" stroke-width="5.4"/>
<circle cx="37.2" cy="152.7" r="1.8" fill="#fff" stroke="#000" stroke-width=".21"/>
<path d="M52.2 150v5.4" fill="none" stroke="#008000" stroke-width="5.4"/>
<circle cx="52.2" cy="152.7" r="1.8" fill="#fff" stroke="#000" stroke-width=".21"/>
<path d="M24.4 90.2h4" fill="none" stroke="#008000" stroke-width="3.9"/>
<circle cx="26.4" cy="90.2" r="1.21" fill="#fff" stroke="#000" stroke-width=".21"/>
<path d="M24.4 97.8h4" fill="none" stroke="#008000" stroke-width="3.9"/>
<circle cx="26.4" cy="97.8" r="1.21" fill="#fff" stroke="#000" stroke-width=".21"/>
<path d="M47.3 128.3h3.9" fill="none" stroke="#008000" stroke-width="3.9"/>
<circle cx="49.3" cy="128.3" r="1.21" fill="#fff" stroke="#000" stroke-width=".21"/>
<path d="M47.3 90.2h3.9" fill="none" stroke="#008000" stroke-width="3.9"/>
<circle cx="49.3" cy="90.2" r="1.21" fill="#fff" stroke="#000" stroke-width=".21"/>
<path d="M47.3 97.8h3.9" fill="none" stroke="#008000" stroke-width="3.9"/>
<circle cx="49.3" cy="97.8" r="1.21" fill="#fff" stroke="#000" stroke-width=".21"/>
<path d="M78.7 65.8v4.6" fill="none" stroke="#008000" stroke-width="4.6"/>
<circle cx="78.7" cy="68.1" r="1.52" fill="#fff" stroke="#000" stroke-width=".21"/>
<path d="M71.1 65.8v4.6" fill="none" stroke="#008000" stroke-width="4.6"/>
<circle cx="71.1" cy="68.1" r="1.52" fill="#fff" stroke="#000" stroke-width=".21"/>
<path d="M63.5 65.8v4.6" fill="none" stroke="#008000" stroke-width="4.6"/>
<circle cx="63.5" cy="68.1" r="1.52" fill="#fff" stroke="#000" stroke-width=".21"/>
<circle cx="57.2" cy="52.2" r="2.15" fill="#008000" stroke="#008000" stroke-width=".21"/>
<circle cx="57.2" cy="52.2" r="1.23" fill="#fff" stroke="#000" stroke-width=".21"/>
<circle cx="57.2" cy="37" r="2.15" fill="#008000" stroke="#008000" stroke-width=".21"/>
<circle cx="57.2" cy="37" r="1.23" fill="#fff" stroke="#000" stroke-width=".21"/>
<path d="M22.4 25.4h5v5h-5z" fill="#008000" stroke="#008000" stroke-width=".21"/>
<circle cx="24.9" cy="27.9" r="1.06" fill="#fff" stroke="#000" stroke-width=".21"/>
<circle cx="32.5" cy="27.9" r="2.48" fill="#008000" stroke="#008000" stroke-width=".21"/>
<circle cx="32.5" cy="27.9" r="1.06" fill="#fff" stroke="#000" stroke-width=".21"/>
<path d="M160.5 72.7h4.5" fill="none" stroke="#008000" stroke-width="4.6"/>
<circle cx="162.8" cy="72.7" r="1.52" fill="#fff" stroke="#000" stroke-width=".21"/>
<path d="M160.5 65.1h4.5" fill="none" stroke="#008000" stroke-width="4.6"/>
<circle cx="162.8" cy="65.1" r="1.52" fill="#fff" stroke="#000" stroke-width=".21"/>
<path d="M160.5 57.4h4.5" fill="none" stroke="#008000" stroke-width="4.6"/>
<circle cx="162.8" cy="57.4" r="1.52" fill="#fff" stroke="#000" stroke-width=".21"/>
<path d="M160.5 49.8h4.5" fill="none" stroke="#008000" stroke-width="4.6"/>
<circle cx="162.8" cy="49.8" r="1.52" fill="#fff" stroke="#000" stroke-width=".21"/>
<path d="M160.5 42.2h4.5" fill="none" stroke="#008000" stroke-width="4.6"/>
<circle cx="162.8" cy="42.2" r="1.52" fill="#fff" stroke="#000" stroke-width=".21"/>
<path d="M160.5 34.6h4.5" fill="none" stroke="#008000" stroke-width="4.6"/>
<circle cx="162.8" cy="34.6" r="1.52" fill="#fff" stroke="#000" stroke-width=".21"/>
<path d="M102.7 91.8h5.8v5.8h-5.8z" fill="#008000" stroke="#008000" stroke-width=".21"/>
<circle cx="105.6" cy="94.7" r="1.35" fill="#fff" stroke="#000" stroke-width=".21"/>
<circle cx="105.6" cy="154.7" r="3.1" fill="#008000" stroke="#008000" stroke-width=".21"/>
<circle cx="105.6" cy="154.7" r="1.35" fill="#fff" stroke="#000" stroke-width=".21"/>
<circle cx="159.7" cy="104.7" r="2.82" fill="#008000" stroke="#008000" stroke-width=".21"/>
<circle cx="159.7" cy="104.7" r="1.52" fill="#fff" stroke="#000" stroke-width=".21"/>
<circle cx="152.1" cy="104.7" r="2.82" fill="#008000" stroke="#008000" stroke-width=".21"/>
<circle cx="152.1" cy="104.7" r="1.52" fill="#fff" stroke="#000" stroke-width=".21"/>
<circle cx="159.7" cy="97.1" r="2.82" fill="#008000" stroke="#008000" stroke-width=".21"/>
<circle cx="159.7" cy="97.1" r="1.52" fill="#fff" stroke="#000" stroke-width=".21"/>
<circle cx="152.1" cy="97.1" r="2.82" fill="#008000" stroke="#008000" stroke-width=".21"/>
<circle cx="152.1" cy="97.1" r="1.52" fill="#fff" stroke="#000" stroke-width=".21"/>
<circle cx="159.7" cy="89.5" r="2.82" fill="#008000" stroke="#008000" stroke-width=".21"/>
<circle cx="159.7" cy="89.5" r="1.52" fill="#fff" stroke="#000" stroke-width=".21"/>
<circle cx="152.1" cy="89.5" r="2.82" fill="#008000" stroke="#008000" stroke-width=".21"/>
<circle cx="152.1" cy="89.5" r="1.52" fill="#fff" stroke="#000" stroke-width=".21"/>
<circle cx="110.2" cy="30.8" r="2.15" fill="#008000" stroke="#008000" stroke-width=".21"/>
<circle cx="110.2" cy="30.8" r="1.23" fill="#fff" stroke="#000" stroke-width=".21"/>
<circle cx="110.2" cy="46" r="2.15" fill="#008000" stroke="#008000" stroke-width=".21"/>
<circle cx="110.2" cy="46" r="1.23" fill="#fff" stroke="#000" stroke-width=".21"/>
<circle cx="142.2" cy="71.9" r="2.15" fill="#008000" stroke="#008000" stroke-width=".21"/>
<circle cx="142.2" cy="71.9" r="1.23" fill="#fff" stroke="#000" stroke-width=".21"/>
<circle cx="104.1" cy="71.9" r="2.15" fill="#008000" stroke="#008000" stroke-width=".21"/>
<circle cx="104.1" cy="71.9" r="1.23" fill="#fff" stroke="#000" stroke-width=".21"/>
<path d="M41.6 25.8v3.9" fill="none" stroke="#008000" stroke-width="4"/>
<circle cx="41.6" cy="27.7" r="1.23" fill="#fff" stroke="#000" stroke-width=".21"/>
<path d="M56.9 25.8v3.9" fill="none" stroke="#008000" stroke-width="4"/>
<circle cx="56.9" cy="27.7" r="1.23" fill="#fff" stroke="#000" stroke-width=".21"/>
<path d="M49.3 25.8v3.9" fill="none" stroke="#008000" stroke-width="4"/>
<circle cx="49.3" cy="27.7" r="1.23" fill="#fff" stroke="#000" stroke-width=".21"/>
<path d="M134 100.9h4.2" fill="none" stroke="#008000" stroke-width="4.3"/>
<circle cx="136.1" cy="100.9" r="1.38" fill="#fff" stroke="#000" stroke-width=".21"/>
<path d="M134 93.3h4.2" fill="none" stroke="#008000" stroke-width="4.3"/>
<circle cx="136.1" cy="93.3" r="1.38" fill="#fff" stroke="#000" stroke-width=".21"/>
<path d="M39.1 80.2h6.6" fill="none" stroke="#008000" stroke-width="6.6"/>
<circle cx="42.4" cy="80.2" r="1.21" fill="#fff" stroke="#000" stroke-width=".21"/>
<path d="M33.4 62.5v6.6" fill="none" stroke="#008000" stroke-width="6.6"/>
<circle cx="33.4" cy="65.8" r="1.21" fill="#fff" stroke="#000" stroke-width=".21"/>
<path d="M51.4 62.5v6.6" fill="none" stroke="#008000" stroke-width="6.6"/>
<circle cx="51.4" cy="65.8" r="1.5" fill="#fff" stroke="#000" stroke-width=".21"/>
<circle cx="147.3" cy="47.5" r="1.04" fill="#008000" stroke="#008000" stroke-width=".21"/>
<circle cx="147.3" cy="47.5" r=".57" fill="#fff" stroke="#000" stroke-width=".21"/>
<circle cx="146.9" cy="37.4" r="1.04" fill="#008000" stroke="#008000" stroke-width=".21"/>
<circle cx="146.9" cy="37.4" r=".57" fill="#fff" stroke="#000" stroke-width=".21"/>
<circle cx="121.3" cy="57.9" r="1.04" fill="#008000" stroke="#008000" stroke-width=".21"/>
<circle cx="121.3" cy="57.9" r=".57" fill="#fff" stroke="#000" stroke-width=".21"/>
<circle cx="98.7" cy="40.3" r="1.04" fill="#008000" stroke="#008000" stroke-width=".21"/>
<circle cx="98.7" cy="40.3" r=".57" fill="#fff" stroke="#000" stroke-width=".21"/>
<circle cx="110.4" cy="58.8" r="1.04" fill="#008000" stroke="#008000" stroke-width=".21"/>
<circle cx="110.4" cy="58.8" r=".57" fill="#fff" stroke="#000" stroke-width=".21"/>
<circle cx="124.3" cy="37" r="1.04" fill="#008000" stroke="#008000" stroke-width=".21"/>
<circle cx="124.3" cy="37" r=".57" fill="#fff" stroke="#000" stroke-width=".21"/>
<circle cx="98.7" cy="31.1" r="1.04" fill="#008000" stroke="#008000" stroke-width=".21"/>
<circle cx="98.7" cy="31.1" r=".57" fill="#fff" stroke="#000" stroke-width=".21"/>
<circle cx="152.4" cy="78.5" r="1.04" fill="#008000" stroke="#008000" stroke-width=".21"/>
<circle cx="152.4" cy="78.5" r=".57" fill="#fff" stroke="#000" stroke-width=".21"/>
<circle cx="101.2" cy="74.7" r="1.04" fill="#008000" stroke="#008000" stroke-width=".21"/>
<circle cx="101.2" cy="74.7" r=".57" fill="#fff" stroke="#000" stroke-width=".21"/>
<circle cx="109.2" cy="52.9" r="1.04" fill="#008000" stroke="#008000" stroke-width=".21"/>
<circle cx="109.2" cy="52.9" r=".57" fill="#fff" stroke="#000" stroke-width=".21"/>
<circle cx="124.7" cy="58.8" r="1.04" fill="#008000" stroke="#008000" stroke-width=".21"/>
<circle cx="124.7" cy="58.8" r=".57" fill="#fff" stroke="#000" stroke-width=".21"/>
<circle cx="81.1" cy="31.5" r="1.04" fill="#008000" stroke="#008000" stroke-width=".21"/>
<circle cx="81.1" cy="31.5" r=".57" fill="#fff" stroke="#000" stroke-width=".21"/>
<circle cx="85.7" cy="65.9" r="1.04" fill="#008000" stroke="#008000" stroke-width=".21"/>
<circle cx="85.7" cy="65.9" r=".57" fill="#fff" stroke="#000" stroke-width=".21"/>
<circle cx="80.7" cy="46.6" r="1.04" fill="#008000" stroke="#008000" stroke-width=".21"/>
<circle cx="80.7" cy="46.6" r=".57" fill="#fff" stroke="#000" stroke-width=".21"/>
<circle cx="100.8" cy="26.5" r="1.04" fill="#008000" stroke="#008000" stroke-width=".21"/>
<circle cx="100.8" cy="26.5" r=".57" fill="#fff" stroke="#000" stroke-width=".21"/>
<circle cx="137.7" cy="32" r="1.04" fill="#008000" stroke="#008000" stroke-width=".21"/>
<circle cx="137.7" cy="32" r=".57" fill="#fff" stroke="#000" stroke-width=".21"/>
<circle cx="164.1" cy="94.8" r="1.04" fill="#008000" stroke="#008000" stroke-width=".21"/>
<circle cx="164.1" cy="94.8" r=".57" fill="#fff" stroke="#000" stroke-width=".21"/>
<circle cx="88.7" cy="72.2" r="1.04" fill="#008000" stroke="#008000" stroke-width=".21"/>
<circle cx="88.7" cy="72.2" r=".57" fill="#fff" stroke="#000" stroke-width=".21"/>
<circle cx="82.4" cy="62.5" r="1.04" fill="#008000" stroke="#008000" stroke-width=".21"/>
<circle cx="82.4" cy="62.5" r=".57" fill="#fff" stroke="#000" stroke-width=".21"/>
<g fill="#800000" stroke="#800000" stroke-width=".21">
<path d="M119.7 49.5h1.6v5.9h-1.6z"/>
<path d="M123.5 49.5h1.6v5.9h-1.6z"/>
<path d="M127.3 49.5h1.6v5.9h-1.6z"/>
<path d="M131.1 49.5h1.6v5.9h-1.6z"/>
<path d="M134.9 49.5h1.6v5.9h-1.6z"/>
<path d="M138.7 49.5h1.6v5.9h-1.6z"/>
<path d="M142.5 49.5h1.6v5.9h-1.6z"/>
<path d="M146.3 49.5h1.6v5.9h-1.6z"/>
<path d="M146.3 21.4h1.6v5.9h-1.6z"/>
<path d="M142.5 21.4h1.6v5.9h-1.6z"/>
<path d="M138.7 21.4h1.6v5.9h-1.6z"/>
<path d="M134.9 21.4h1.6v5.9h-1.6z"/>
<path d="M131.1 21.4h1.6v5.9h-1.6z"/>
<path d="M127.3 21.4h1.6v5.9h-1.6z"/>
<path d="M123.5 21.4h1.6v5.9h-1.6z"/>
<path d="M119.7 21.4h1.6v5.9h-1.6z"/>
<path d="M147.8 63h5.5v4.8h-5.5z"/>
<path d="M147.8 71.5h5.5v4.8h-5.5z"/>
<path d="M151.3 153.5h4.5v4.5h-4.5z"/>
<path d="M140.8 153.5h4.5v4.5h-4.5z"/>
<path d="M158.1 117.7h4.8v6.9h-4.8z"/>
<path d="M158.1 136.6h4.8v6.9h-4.8z"/>
<path d="M143.3 124.8h5.4v4.8h-5.4z"/>
<path d="M143.3 116.3h5.4v4.8h-5.4z"/>
<path d="M113.2 108.1h7.7v3.8h-7.7z"/>
<path d="M113.2 115.7h7.7v3.8h-7.7z"/>
<path d="M90.4 108.1h7.6v3.8h-7.6z"/>
<path d="M90.4 115.7h7.6v3.8h-7.6z"/>
</g>
<g fill="none" stroke="#800000" stroke-width=".93">
<path d="M24.9 27.9l.1 11.2 26.4 26.4v.3M32.5 27.9v.3h3l5 5h16.7M49.3 27.7v-.4l5-5h3.8l2.1 2.1v5l22.2 22.2v10.9M56.9 27.7l.3 .1v9.6l-3.3 3.4v12.9l1.7 1.7h2.9l4.8 4.8M81.1 31.5v12.2l4.6 4.6v17.6M98.7 31.1h.9l6.7-6.7 14.2-.1v-2l2.5-2.5h25.2l8.8 8.8v23l5.8 5.8-.4 .1-5.4 5.5v11.7l-3.8 3.8h-.8M100.8 26.5h-18l-4.2 4.2v13l2.1 2.1v.8M124.3 24.3v12.7M128.1 24.3l.4 .1v2.1l18.4 18.5h1.3l1.6 1.6v12.6l-4.2 4.2v9.6l-5.8 5.9h-29.4l-4.5 4.6v10.9l-.3 .3M131.9 24.3h15.2l-.2 .5v12.6M137.7 32l13.8 13.8v18.4l-.9 1.2M57.2 52.2v.3h.9l9.6 9.6h5l6 6"/>
<path d="M98.7 40.3v6.8l11.7 11.7M104 55.6l-14.1 14.1h-2.1l-6.2 6.3M110.2 46l-.2-.2h-2.5l-7.9-8h-1.7l-1.7 1.7v8.4l14.2 14.2h17.7l7.9-7.9v-1.3l-.3-.4h11.4l.2-.4v-4.6M121.3 57.9v-.8l3-2.9v-9.2l-14.1-14.2-.2 .3h-7.9l-7.6 7.6v18.8l1.2 1.1-.3 .2v.8l-14.7 14.7h-11.3l-5.9-5.9v-.3M124.1 58.6l.2 .2h.4M128.1 52.5v2.1l-5.9 5.9h-1.7l-7.5-7.6h-3.8M128.1 52.5h.1M63.3 60.2l7.8 7.9M63.3 60.2l-3.5 3.6v8l4.1 4.2h17.7M81.6 76v39.3l23.8 23.9v15.1l.2 .4h.3h29.7l4.6 4.6h9.6l3.7-3.6 .1-1 10.5-10.4v-19.7l-3.4-3.4-.2-.1 6.1-6.2v-24.3l-5.5-5.4h-2.9l-4.2 4.2-1.9 .1M101.2 74.7v8.4l-13.8 13.8v21.8l2.1 2.1h24.3l3.3-3.2M104.1 71.9l-.3 .3h-15.1"/>
<path d="M142.2 71.9l-.3 .3h-27.3l-25.5 25.5v14.7l5.1 5.2M150.6 73.9l-2.9 2.9v22.2l-9.6 9.6v33.2l4.6 4.5v9.3l.3 .1M111.6 82.5l5.1 5.2v22.2l.4 .1M136.1 93.3l5.8 5.7v3.4l-10.9 10.8h-18.5l-2.9-2.9h-15.1l-.3-.3M142.1 82.5l-.2 .2h-2.1l-9.2 9.2v3.3l5.5 5.7M164.1 94.8v14.3l-17.2 17.1M152.1 104.7l-6 6-.1 8M146.9 126.2l-.9 1zM146.9 126.2l13.4 13.5 .2 .3"/>
</g>
<g fill="none" stroke="#800000" stroke-width="1.9">
<path d="M21.8 19.5h98.4M21.8 34.5h1M21.8 38.3h1M21.8 36.4h1M21.8 32.7h1M21.8 23.3h17.1M21.8 21.4h30.4M27.2 34.5h27.2M27.2 36.4h11.3M27.2 32.7h12.1M27.2 38.3h9.6M29.1 30.8h.3"/>
<path d="M29.1 25.2h.3M32.5 25.2h.1M32.5 23.7v8.4M32.5 30.8h.1M32.5 28.9h.1M32.5 27v.1M35.6 30.8h2.5M35.7 25.2h2.2M36.6 28.9a4.2 4.2 0 0 0-2.4-4.8 4.2 4.2 0 0 0-5.1 1.4v-.8l-1-1h-6.3v-5.1h99.4l-1.1 1.1h-1.1l-1 1v1.5h-12.2l-.8 .4-2.1 2.1a2.64 2.64 0 0 0-3.8-.4h-16.7l-.8 .4-4.8 4.8-.4 .8v12.4l-14-14.1v-4.6l-.4-.8-2.7-2.7-.8-.3h-4.6l-.8 .3-2 2a3.7 3.7 0 0 0-5.5 2.5v5.5a3.8 3.8 0 0 0 3.6 3 3.8 3.8 0 0 0 3.7-3v-3.7l.3-.3v3.5a3.6 3.6 0 0 0 2.7 3.3h-.2l-2.2 2.2v3l2.2 2.2h3l2.2-2.2v-3l-2.2-2.2h-.9a3.7 3.7 0 0 0 1.9-1.2l20.5 20.5v8.2l-.5 1.1a3.8 3.8 0 0 0-3.4 .7l-1-1 .8-.8M36.6 28.9a4.2 4.2 0 0 1-3.3 3.1 4.2 4.2 0 0 1-4.2-1.7v.8l-1 1h-.9v6.1l20.7 20.7a5 5 0 0 1 8.5 2.7v8.5M36.6 28.9h1.3M36.6 27h1.3"/>
<path d="M36.7 27.9h-4.2M36.7 38.4h.1M36.7 38.4l-1.1 2.7v2.9l1.1 2.7M38.5 23.7a3.8 3.8 0 0 1 3.9-1.6 3.8 3.8 0 0 1 2.9 2.9v5.5a3.8 3.8 0 0 1-3.7 3 3.8 3.8 0 0 1-3.7-3v-5.5zM38.7 36.3h.1M38.7 36.3l-2 2.1M41.2 35h.1M41.2 35l-2.5 1.3M43.9 32.7h3.1M44.1 34.7l2.8 .8M44.1 34.7h.1M44.1 34.7l-2.9 .3"/>
<path d="M44.4 23.3h2.1M45.2 30.8h.5M45.3 28.9h.3M45.3 27h.3M45.3 25.2h.3M46.9 35.5h.1M46.9 35.5l2.3 1.7M48.1 36.4h5.4M49.2 37.2l1.5 2.5M49.2 37.2v.1M49.8 38.3h3.7M50.7 39.7h.1"/>
<path d="M50.7 39.7l.5 2.8-.5 2.9M51.5 32.7h3.1M52.8 30.8h.5M52.9 28.9h.3M52.9 27h.3M53.2 27.7h3.7M53.5 37h7.4M57.2 38.3h.1M57.2 37v3.7M59.1 32.7h1.2M60 34.5h2.2M60.2 21.4h57.8"/>
<path d="M60.9 38.3h5M60.9 36.4h3.2M62.1 23.3h42.2M62.4 27h16.8M62.4 25.2h18.7M62.7 28.9h14.6M64.6 30.8h11.8M66.5 32.7h9.9M68.3 34.5h8.1M70.2 36.4h6.2M72.1 38.3h4.3M99.9 36.4h12.7"/>
<path d="M100.5 38.3h14M101.7 34.5h9.1M104.8 28.9h2M106.7 27h11.3M108.6 34.5l-1.1-1.2h-4.5l-4.3 4.3a2.74 2.74 0 0 1 2.5 1.5 2.74 2.74 0 0 1-.3 3M110.7 34.5l11.4 11.3v2.1l-.1-.1h-3l-1 1v6l-3.8-3.7-.8-.4h-2.5a2.71 2.71 0 0 0-4.3 1.2l-5.7-5.8v-4M113.5 28.9h5.4M113.9 30.8h8.2M115.1 32.7h7M116.9 34.5h5.2M118.8 36.4h2.8M120.7 38.3h1.1"/>
<path d="M122.1 28.9l-.1 .1h-3l-1-1v-1.4h-10.8l-2.4 2.4h2l1.8-1.9h3.1l2.2 2.2v2.2l12.2 12.2 .3 .8v3.4l.2-.1h3l.4 .4 .4-.4h3l.5 .3a4 4 0 0 1 3.3-.2l.5 .2a4 4 0 0 1 3.3-.2l.5 .2a4 4 0 0 1 3.3-.2l.4 .3 .9-.4h1.6v-.3l-.4-.4h-.8l-.8-.3-17.8-17.8h-1.3l-.2-.1M122.1 28.9v6.4a2.77 2.77 0 0 0 .3 3.7 2.77 2.77 0 0 0 3.8 0 2.77 2.77 0 0 0 .2-3.7v-6.4M122.1 28.9h.1M126.4 34.5h7M126.4 32.7h5.1M126.4 30.8h3.3M126.4 28.9h.1M126.7 38.3h10.5M127 36.4h8.3M133.9 28.9h.3M134.2 28.9l-.5-.2 1.7 1.7a2.75 2.75 0 0 1 3-1.2 2.75 2.75 0 0 1 2 2.4l13 13 .3 .8v15.9h.3l.9 .9 .2-.5 2-1.9a3.9 3.9 0 0 1 .1-4.8l-2.1-2.1-.3-.8v-22.6l-5.2-5.1v3.1a1.71 1.71 0 0 1-1.4 1.5l-2.5-.1M134.2 28.9h3"/>
<path d="M135.7 28.9h.1M135.7 25.2h.1M135.7 27v.1M135.7 24.4v4.6M137.2 28.9l.4-.3 .4 .3M137.2 28.9h.8M138 28.9h3M139.5 28.9h.1M139.5 27v.1M139.5 25.2h.1M139.5 24.4v4.6M140.2 30.8h14.6"/>
<path d="M141 28.9l.4-.3 .5 .3M141 28.9h.9M141.5 32.7h13.3M141.9 28.9a4 4 0 0 0 3.3-.2l.5 .2M143.3 34.5h11.5M143.3 28.9h.1M143.3 27v.1M143.3 25.2h.1M143.3 24.4v4.6M144.8 28.9h.9M145.2 36.4h9.6M147.1 38.3h7.7"/>
<path d="M147.1 24.3l-15.2 .1M147.1 24.3l.1 .1M147.1 24.3v4.7M147.1 28.9h.1M147.1 27l.1 .1M147.1 25.2h.1M148.6 28.9h5.6M149.6 27h2.7M149.6 25.2h.9M21.8 58.9h8.2M21.8 57h18M21.8 55.1h16.2"/>
<path d="M21.8 53.3h14.3M21.8 51.4h12.4M21.8 49.5h10.5M21.8 47.6h8.7M21.8 45.8h6.8M21.8 43.9h4.9M21.8 42h3M21.8 40.2h1.3M29.1 40.2h6.9M29.6 59.2a5 5 0 0 1 5.4-1.4 5 5 0 0 1 3.4 4.4v7.2a5 5 0 0 1-5 4.7 5 5 0 0 1-5-4.7v-7.2a5 5 0 0 1 1.2-3zM31 42h4.6M32.9 43.9h2.7"/>
<path d="M33.4 57.6v16.5M33.4 58.9h.1M34.7 45.8h1.6M36.6 47.6h1M36.7 46.7h.1M36.7 46.7l2 2.1M36.8 58.9h4.9M38.5 49.5h1.5M38.7 48.8h.1M38.7 48.8l2.5 1.3M40.3 51.4h13.2M41.2 50.1h.1"/>
<path d="M41.2 50.1l2.9 .3M42.2 53.3h11.3M44.1 55.1h10.8M44.1 50.4h.1M46 57h13.5M46.9 49.6l-2.8 .8M46.9 49.6h.1M47 49.5h7.7M47.8 58.9h.2M49.2 47.8l-2.3 1.8M49.2 47.8v.1M49.3 47.6h26"/>
<path d="M50.5 45.8h22.9M50.7 45.4l-1.5 2.4M50.7 45.4h.1M50.8 40.2h4.3M51 43.9h20.5M51.1 42h18.6M54.8 58.9h6.6M57.2 40.2h.1M59.3 40.2h8.5M59.7 49.5h17.5M60.9 51.4h18.1M61.9 53.3h18.3"/>
<path d="M63.8 55.1h7.4M65.7 57h3.6M67.5 58.9h1.5M73.9 40.2h2.5M74.4 55.1h5.8M75.8 42h.6M76.3 57h3.9M76.6 58.9h3.6M96.7 53.3h5.2M96.7 51.4h3.3M96.7 49.5h1.4M97.3 55.1h6.4"/>
<path d="M99.1 57h6.5M99.5 58.9h8M100.9 45.8h5.6M100.9 43.9h6.2M100.9 42h17.4M101.5 40.2h14.9M102.4 47.6h4.2M104.3 49.5h4.2M106.1 51.4h.8M106.5 46h7.4M110.2 47.6v.1M110.2 42.3v7.4"/>
<path d="M110.2 46h.1M110.2 49.5h.1M110.2 45.8h.1M110.2 43.9h.1M110.8 55.1h1.3M111.9 49.5h6.1M112.6 57h1.4M113.2 58.9h2.7M113.3 43.9h6.8M113.8 47.6h8.3M113.9 45.8h8.1M114.5 51.4h3.5"/>
<path d="M116.4 53.3h1.6M122.6 40.2h16.4M124.4 42h16.5M126.2 43.9h16.6M126.4 47.6h21.3M126.4 45.8h18.3M127.4 58.9h19.7M129.7 57h.5M133.5 57h.7M135.7 47.8v9.3M135.7 57h.1M135.7 55.1v.1"/>
<path d="M135.7 53.3h.1M135.7 51.4h.1M135.7 49.5h.1M137.2 57h.8M139.5 52.5h.1M139.5 47.8v9.3M139.5 49.5h.1M139.5 57h.1M139.5 55.1v.1M139.5 53.3h.1M139.5 51.4h.1M141 57h.8"/>
<path d="M143.3 52.5h.1M143.3 47.8v9.3M143.3 57h.1M143.3 55.1v.1M143.3 51.4h.1M143.3 53.3h.1M143.3 49.5h.1M144.8 57h.8M147.1 52.5h-11.4M147.1 52.5h.1M147.1 47.8v9.3M147.1 49.5h.1"/>
<path d="M147.1 57h.1M147.1 55.1l.1 .1M147.1 53.3h.1M147.1 51.4h.1M148.9 40.2h5.9M150.8 42h4M152.7 43.9h2.1M153.7 58.9h3M153.7 57h2.8M153.7 55.1h3.4M153.7 53.3h1.8M153.7 51.4h1.1"/>
<path d="M153.7 49.5h1.1M153.7 47.6h1.1M153.7 45.8h1.1M21.8 68.2h6.6M21.8 79.5h12.3M21.8 77.6h13M21.8 75.7h15.1M21.8 73.9h10.1M21.8 72h7.5M21.8 70.1h6.7M21.8 66.4h6.6M21.8 64.5h6.6"/>
<path d="M21.8 62.6h6.6M21.8 60.7h6.9M28.4 65.8h10M33.4 65.8h.1M33.4 73.9h.1M33.4 72h.1M33.4 70.1h.1M33.4 68.2v.1M33.4 66.4h.1M33.4 64.5h.1M33.4 62.6h.1M33.4 60.7v.1"/>
<path d="M34.9 73.9h14.9M37.5 72h9.7M38 60.7h5.6M38.3 70.1h8.1M38.4 68.2h8M38.4 66.4h8M38.4 64.5h8M38.4 62.6h7M46.4 70.1v-6.5l-23.3-23.3-.3-.8v-7.4h-1v51.3h13.4a5 5 0 0 1 2.9-8.2h8.6a5 5 0 0 1 2.9 8.2h5l1.5 1.5v38.8h15.2v38.9h96v-86.5l-1.5 .6h-6.1l-1.2-.5-4.1 4.1a2.69 2.69 0 0 1-4.5-.5v5.7a4.5 4.5 0 0 1 6 1.4 4.6 4.6 0 0 1 6.4-1.3 4.6 4.6 0 0 1 1.1 6.5 2.76 2.76 0 0 1 3 1.2 2.76 2.76 0 0 1-.1 3.2v13l-.4 .8-5.7 5.7v10.3M46.4 70.1a5.1 5.1 0 0 0 5 4.1 5.1 5.1 0 0 0 5-4.1M47.9 75.7h19.9M50 77.6h49.1"/>
<path d="M50.7 79.5h48.4M52.9 73.9h8.5M55.6 72h4.2M56 60.7h7.3M56.4 68.2h3.1M56.4 70.1h3.1M56.4 66.4h3.1M56.4 64.5h3.3M56.4 62.6h4.7M65.6 73.9h.3M76.1 60.8a3.9 3.9 0 0 0-2.8-6.1 3.9 3.9 0 0 0-4.1 5.3h-.6l-7.7-7.8v-1.5l-2.2-2.2h-3l-2.2 2.2v3.1l2.2 2.1h2.7l6 5.9a4 4 0 0 0-4.9 3.2v6.2a4.1 4.1 0 0 0 6.3 2.6l2.4 2.3 .8 .4h12.1l.8-.4 4-4a2.74 2.74 0 0 0 1.5 2.6 2.74 2.74 0 0 0 3-.3h8.1v.8l.6 1.2v5.8l-13.5 13.5-.4 .8v22.6l.4 .8 2.7 2.7 .8 .4h25.1l.8-.4 1.4-1.4h5.2l1-1v-4.8h8.8l.8-.3 3.7-3.7v30.8l.4 .8 4.2 4.3v4.5h-.4l-1 1v5.9l1 1h5.9l1-1v-5.9l-1-1h-1.1v-5.6l1.5 .1M76.1 60.7h4.1"/>
<path d="M82.3 75.7h16.4M84.2 73.9h2.3M91.7 66.4h51.8M93.6 64.5h49.9M95.4 62.6h24.7M98.9 60.8l-1.1 1-1.4 .6h-.8l-7 7h.6l1.2 .6h10.4l1.8-1.8M98.9 60.8a3.9 3.9 0 0 0-2.2-5.9v-7.1l.2 .5 10.8 10.8a2.78 2.78 0 0 0 2.9 2.5 2.78 2.78 0 0 0 2.7-2.7 2.78 2.78 0 0 0-2.5-2.9l-.6-.5 .7-.4h1.2l7.2 7.2 .8 .3h2.5l.8-.3 .8-.8a2.79 2.79 0 0 0 3.2-3.2l1.2-1.2h1l.4-.4 .4 .4h3l.5-.3a3.7 3.7 0 0 0 3.3 .2l.5-.2a3.7 3.7 0 0 0 3.3 .2l.5-.2a3.7 3.7 0 0 0 3.3 .2l.4-.3 .9 .4h1.6v1.2l-3.9 3.9-.3 .7v5.3h-53.7M98.9 60.7h9.6M103.4 79.5h.9M103.4 77.6h2.8M103.8 75.7h4.2M105.6 68.2l2.2 2.2v3l-2.2 2.2h-1.8l-.4 .8v3.9l10-9.9 .8-.4h24.7l1.8-1.8"/>
<path d="M107.4 73.9h2.5M107.5 70.1h6.5M107.8 72h4M112.4 60.7h5.3M122.6 62.6h21M126.6 60.7h18.6M153.7 60.7h2.4M155.3 79.5h12M157.1 77.6h10.2M21.8 83.2h13.3M21.8 81.3h12.4M26.4 90.2h.2l3 2.9h.4l7.1 7.2 .1 52.4"/>
<path d="M49.7 83.2h48.3M50.6 81.3h48.5M56.1 98.2h29.1M56.1 96.3h29.2M56.1 94.5h30.7M56.1 92.6h32.6M56.1 90.7h34.4M56.1 88.8h36.3M56.1 87h38.2M56.1 85.1h40.1M149.9 85.1h.9M149.9 83.2h17.4"/>
<path d="M149.9 81.3h17.4M152.1 84.9v4.6M152.1 88.8v.1M152.1 87h.1M152.1 85.1h.1M153.4 85.1h4.9M161.1 85.1h6.2M163.6 87h3.7M164.1 90.7h3.2M164.2 88.8h3.1M165.7 92.6h1.6M166.3 98.2h1"/>
<path d="M166.4 96.3h.9M166.8 94.5h.5M56.1 118.8h11.5M56.1 116.9h9.5M56.1 115.1h8.6M56.1 113.2h8.4M56.1 111.3h8.5M56.1 109.5h9.3M56.1 107.6h11.1M56.1 105.7h29.1M56.1 103.8h29.1M56.1 102h29.1"/>
<path d="M56.1 100.1h29.1M74.7 118.8h10.5M75.1 107.6h10.1M76.7 116.9h8.5M76.8 109.5h8.4M77.5 115.1h7.7M77.6 111.3h7.6M77.8 113.2h7.4M122.6 118.8h13.3M122.6 116.9h13.3M132.2 115.1h3.7M134.1 113.2h1.8"/>
<path d="M160.2 118.8h.5M160.2 116.9h.5M161.2 115.1h6.1M163 113.2h4.3M164.4 116.9h2.9M164.6 118.8h2.7M164.9 111.3h2.4M166.3 109.5h1M166.3 107.6h1M166.3 105.7h1M166.3 103.8h1M166.3 102h1"/>
<path d="M166.3 100.1h1M49.3 128.3v21.8l2.5 2.5 .4 .1M56.1 122.6h32.1M56.1 120.7h30.2M71.3 126.3h64.6M71.3 139.4h64.6M71.3 137.5h64.6M71.3 135.7h64.6M71.3 133.8h64.6M71.3 131.9h64.6M71.3 130h64.6M71.3 128.2h64.6"/>
<path d="M71.3 124.4h64.6M115.1 122.6h20.8M122.1 120.7h13.8M150.4 126.3h16.9M151.8 124.4h4.6M151.9 128.2h15.4M153 135.7h.2M153.3 137.5h1.8M153.4 139.4h3M153.5 138.5l-.5 2.9M153.5 138.5h.1M153.7 122.6h2.7"/>
<path d="M153.8 130h13.5M155.5 120.7h.9M155.7 131.9h11.6M157.5 133.8h9.8M157.8 126.3a1.71 1.71 0 0 1-1.4-1.5v-3.4h8.2v3.4a1.71 1.71 0 0 1-1.5 1.5M160.2 124.4h.5M160.2 122.6h.5M160.2 120.7h.5M160.7 126.3v-10.3h2.4a1.71 1.71 0 0 1 1.5 1.5v3.4h-8.2v-1l-6 5.9v.9l8.2 8.2h5l1 1v8.3l-1 1h-6.2l-1-1v-5.4l-3.9-3.9 .5 .8 .5 2.8M164.4 135.7h2.9M164.6 139.4h2.7M164.6 137.5h2.7"/>
<path d="M164.6 124.4h2.7M164.6 122.6h2.7M164.6 120.7h2.7M71.3 158.1h31.3M71.3 156.3h29.7M71.3 154.4h29.7M71.3 152.5h30M71.3 150.6h31.8M71.3 148.8h69.2M71.3 146.9h68.9M71.3 145h67M71.3 143.2h65.1"/>
<path d="M71.3 141.3h64.6M101 154.7h9.2M105.6 150.1v9.2M105.6 154.7h.1M105.6 158.1v.1M105.6 156.3h.1M105.6 154.4h.1M105.6 152.5h.1M105.6 150.6v.1M108.1 150.6h32.4M108.7 158.1h30.4M110 152.5h29.3"/>
<path d="M110.2 156.3h28.9M110.2 154.4h28.9M144.9 150.6h22.4M144.9 148.8h22.4M144.9 146.9h22.4M146.4 146.3v.1M146.7 152.5h3.1M147 158.1h2.6M147 156.3h2.6M147 154.4h2.6M149.2 145.6l-2.8 .7M149.2 145.6h.1"/>
<path d="M149.8 145h7.4M149.9 152.4l.7-.5 .4-.1h2.4v7.9h-2.4a1.71 1.71 0 0 1-1.4-1.5v-2.3h7.9v2.3a1.71 1.71 0 0 1-1.5 1.5h-2.3v-7.9h2.3a1.71 1.71 0 0 1 1.5 1.4v2.4h-7.9v-2.4zM151.5 143.8l-2.3 1.8M151.5 143.8h.1M151.9 143.2h4.5M153 141.4l-1.5 2.4M153 141.4h.1M153 141.3h3.4M153.4 158.1h.3M153.4 156.3h.3M153.4 154.4h.3M153.4 152.5h.3"/>
<path d="M157.2 152.5h10.1M157.5 158.1h9.8M157.5 156.3h9.8M157.5 154.4h9.8M163.7 145h3.6M164.6 143.2h2.7M164.6 141.3h2.7M71.3 161.9h96M71.3 160h96"/>
<circle cx="110.2" cy="46" r="4"/>
<circle cx="71.1" cy="113.1" r="6.8"/>
<circle cx="105.6" cy="154.7" r="5"/>
</g>
<circle cx="72.8" cy="58.6" r="2.12" fill="#008000" stroke="#008000" stroke-width=".21"/>
<circle cx="72.8" cy="58.6" r="1.35" fill="#fff" stroke="#000" stroke-width=".21"/>
<circle cx="95.7" cy="58.6" r="2.12" fill="#008000" stroke="#008000" stroke-width=".21"/>
<circle cx="95.7" cy="58.6" r="1.35" fill="#fff" stroke="#000" stroke-width=".21"/>
<circle cx="142.1" cy="82.5" r="2.15" fill="#008000" stroke="#008000" stroke-width=".21"/>
<circle cx="142.1" cy="82.5" r="1.23" fill="#fff" stroke="#000" stroke-width=".21"/>
<circle cx="111.6" cy="82.5" r="2.15" fill="#008000" stroke="#008000" stroke-width=".21"/>
<circle cx="111.6" cy="82.5" r="1.23" fill="#fff" stroke="#000" stroke-width=".21"/>
<path d="M37.2 150v5.4" fill="none" stroke="#008000" stroke-width="5.4"/>
<circle cx="37.2" cy="152.7" r="1.8" fill="#fff" stroke="#000" stroke-width=".21"/>
<path d="M52.2 150v5.4" fill="none" stroke="#008000" stroke-width="5.4"/>
<circle cx="52.2" cy="152.7" r="1.8" fill="#fff" stroke="#000" stroke-width=".21"/>
<path d="M24.4 90.2h4" fill="none" stroke="#008000" stroke-width="3.9"/>
<circle cx="26.4" cy="90.2" r="1.21" fill="#fff" stroke="#000" stroke-width=".21"/>
<path d="M24.4 97.8h4" fill="none" stroke="#008000" stroke-width="3.9"/>
<circle cx="26.4" cy="97.8" r="1.21" fill="#fff" stroke="#000" stroke-width=".21"/>
<path d="M47.3 128.3h3.9" fill="none" stroke="#008000" stroke-width="3.9"/>
<circle cx="49.3" cy="128.3" r="1.21" fill="#fff" stroke="#000" stroke-width=".21"/>
<path d="M47.3 90.2h3.9" fill="none" stroke="#008000" stroke-width="3.9"/>
<circle cx="49.3" cy="90.2" r="1.21" fill="#fff" stroke="#000" stroke-width=".21"/>
<path d="M47.3 97.8h3.9" fill="none" stroke="#008000" stroke-width="3.9"/>
<circle cx="49.3" cy="97.8" r="1.21" fill="#fff" stroke="#000" stroke-width=".21"/>
<path d="M78.7 65.8v4.6" fill="none" stroke="#008000" stroke-width="4.6"/>
<circle cx="78.7" cy="68.1" r="1.52" fill="#fff" stroke="#000" stroke-width=".21"/>
<path d="M71.1 65.8v4.6" fill="none" stroke="#008000" stroke-width="4.6"/>
<circle cx="71.1" cy="68.1" r="1.52" fill="#fff" stroke="#000" stroke-width=".21"/>
<path d="M63.5 65.8v4.6" fill="none" stroke="#008000" stroke-width="4.6"/>
<circle cx="63.5" cy="68.1" r="1.52" fill="#fff" stroke="#000" stroke-width=".21"/>
<circle cx="57.2" cy="52.2" r="2.15" fill="#008000" stroke="#008000" stroke-width=".21"/>
<circle cx="57.2" cy="52.2" r="1.23" fill="#fff" stroke="#000" stroke-width=".21"/>
<circle cx="57.2" cy="37" r="2.15" fill="#008000" stroke="#008000" stroke-width=".21"/>
<circle cx="57.2" cy="37" r="1.23" fill="#fff" stroke="#000" stroke-width=".21"/>
<path d="M22.4 25.4h5v5h-5z" fill="#008000" stroke="#008000" stroke-width=".21"/>
<circle cx="24.9" cy="27.9" r="1.06" fill="#fff" stroke="#000" stroke-width=".21"/>
<circle cx="32.5" cy="27.9" r="2.48" fill="#008000" stroke="#008000" stroke-width=".21"/>
<circle cx="32.5" cy="27.9" r="1.06" fill="#fff" stroke="#000" stroke-width=".21"/>
<path d="M160.5 72.7h4.5" fill="none" stroke="#008000" stroke-width="4.6"/>
<circle cx="162.8" cy="72.7" r="1.52" fill="#fff" stroke="#000" stroke-width=".21"/>
<path d="M160.5 65.1h4.5" fill="none" stroke="#008000" stroke-width="4.6"/>
<circle cx="162.8" cy="65.1" r="1.52" fill="#fff" stroke="#000" stroke-width=".21"/>
<path d="M160.5 57.4h4.5" fill="none" stroke="#008000" stroke-width="4.6"/>
<circle cx="162.8" cy="57.4" r="1.52" fill="#fff" stroke="#000" stroke-width=".21"/>
<path d="M160.5 49.8h4.5" fill="none" stroke="#008000" stroke-width="4.6"/>
<circle cx="162.8" cy="49.8" r="1.52" fill="#fff" stroke="#000" stroke-width=".21"/>
<path d="M160.5 42.2h4.5" fill="none" stroke="#008000" stroke-width="4.6"/>
<circle cx="162.8" cy="42.2" r="1.52" fill="#fff" stroke="#000" stroke-width=".21"/>
<path d="M160.5 34.6h4.5" fill="none" stroke="#008000" stroke-width="4.6"/>
<circle cx="162.8" cy="34.6" r="1.52" fill="#fff" stroke="#000" stroke-width=".21"/>
<path d="M102.7 91.8h5.8v5.8h-5.8z" fill="#008000" stroke="#008000" stroke-width=".21"/>
<circle cx="105.6" cy="94.7" r="1.35" fill="#fff" stroke="#000" stroke-width=".21"/>
<circle cx="105.6" cy="154.7" r="3.1" fill="#008000" stroke="#008000" stroke-width=".21"/>
<circle cx="105.6" cy="154.7" r="1.35" fill="#fff" stroke="#000" stroke-width=".21"/>
<circle cx="159.7" cy="104.7" r="2.82" fill="#008000" stroke="#008000" stroke-width=".21"/>
<circle cx="159.7" cy="104.7" r="1.52" fill="#fff" stroke="#000" stroke-width=".21"/>
<circle cx="152.1" cy="104.7" r="2.82" fill="#008000" stroke="#008000" stroke-width=".21"/>
<circle cx="152.1" cy="104.7" r="1.52" fill="#fff" stroke="#000" stroke-width=".21"/>
<circle cx="159.7" cy="97.1" r="2.82" fill="#008000" stroke="#008000" stroke-width=".21"/>
<circle cx="159.7" cy="97.1" r="1.52" fill="#fff" stroke="#000" stroke-width=".21"/>
<circle cx="152.1" cy="97.1" r="2.82" fill="#008000" stroke="#008000" stroke-width=".21"/>
<circle cx="152.1" cy="97.1" r="1.52" fill="#fff" stroke="#000" stroke-width=".21"/>
<circle cx="159.7" cy="89.5" r="2.82" fill="#008000" stroke="#008000" stroke-width=".21"/>
<circle cx="159.7" cy="89.5" r="1.52" fill="#fff" stroke="#000" stroke-width=".21"/>
<circle cx="152.1" cy="89.5" r="2.82" fill="#008000" stroke="#008000" stroke-width=".21"/>
<circle cx="152.1" cy="89.5" r="1.52" fill="#fff" stroke="#000" stroke-width=".21"/>
<circle cx="110.2" cy="30.8" r="2.15" fill="#008000" stroke="#008000" stroke-width=".21"/>
<circle cx="110.2" cy="30.8" r="1.23" fill="#fff" stroke="#000" stroke-width=".21"/>
<circle cx="110.2" cy="46" r="2.15" fill="#008000" stroke="#008000" stroke-width=".21"/>
<circle cx="110.2" cy="46" r="1.23" fill="#fff" stroke="#000" stroke-width=".21"/>
<circle cx="142.2" cy="71.9" r="2.15" fill="#008000" stroke="#008000" stroke-width=".21"/>
<circle cx="142.2" cy="71.9" r="1.23" fill="#fff" stroke="#000" stroke-width=".21"/>
<circle cx="104.1" cy="71.9" r="2.15" fill="#008000" stroke="#008000" stroke-width=".21"/>
<circle cx="104.1" cy="71.9" r="1.23" fill="#fff" stroke="#000" stroke-width=".21"/>
<path d="M41.6 25.8v3.9" fill="none" stroke="#008000" stroke-width="4"/>
<circle cx="41.6" cy="27.7" r="1.23" fill="#fff" stroke="#000" stroke-width=".21"/>
<path d="M56.9 25.8v3.9" fill="none" stroke="#008000" stroke-width="4"/>
<circle cx="56.9" cy="27.7" r="1.23" fill="#fff" stroke="#000" stroke-width=".21"/>
<path d="M49.3 25.8v3.9" fill="none" stroke="#008000" stroke-width="4"/>
<circle cx="49.3" cy="27.7" r="1.23" fill="#fff" stroke="#000" stroke-width=".21"/>
<path d="M134 100.9h4.2" fill="none" stroke="#008000" stroke-width="4.3"/>
<circle cx="136.1" cy="100.9" r="1.38" fill="#fff" stroke="#000" stroke-width=".21"/>
<path d="M134 93.3h4.2" fill="none" stroke="#008000" stroke-width="4.3"/>
<circle cx="136.1" cy="93.3" r="1.38" fill="#fff" stroke="#000" stroke-width=".21"/>
<path d="M39.1 80.2h6.6" fill="none" stroke="#008000" stroke-width="6.6"/>
<circle cx="42.4" cy="80.2" r="1.21" fill="#fff" stroke="#000" stroke-width=".21"/>
<path d="M33.4 62.5v6.6" fill="none" stroke="#008000" stroke-width="6.6"/>
<circle cx="33.4" cy="65.8" r="1.21" fill="#fff" stroke="#000" stroke-width=".21"/>
<path d="M51.4 62.5v6.6" fill="none" stroke="#008000" stroke-width="6.6"/>
<circle cx="51.4" cy="65.8" r="1.5" fill="#fff" stroke="#000" stroke-width=".21"/>
<circle cx="147.3" cy="47.5" r="1.04" fill="#008000" stroke="#008000" stroke-width=".21"/>
<circle cx="147.3" cy="47.5" r=".57" fill="#fff" stroke="#000" stroke-width=".21"/>
<circle cx="146.9" cy="37.4" r="1.04" fill="#008000" stroke="#008000" stroke-width=".21"/>
<circle cx="146.9" cy="37.4" r=".57" fill="#fff" stroke="#000" stroke-width=".21"/>
<circle cx="121.3" cy="57.9" r="1.04" fill="#008000" stroke="#008000" stroke-width=".21"/>
<circle cx="121.3" cy="57.9" r=".57" fill="#fff" stroke="#000" stroke-width=".21"/>
<circle cx="98.7" cy="40.3" r="1.04" fill="#008000" stroke="#008000" stroke-width=".21"/>
<circle cx="98.7" cy="40.3" r=".57" fill="#fff" stroke="#000" stroke-width=".21"/>
<circle cx="110.4" cy="58.8" r="1.04" fill="#008000" stroke="#008000" stroke-width=".21"/>
<circle cx="110.4" cy="58.8" r=".57" fill="#fff" stroke="#000" stroke-width=".21"/>
<circle cx="124.3" cy="37" r="1.04" fill="#008000" stroke="#008000" stroke-width=".21"/>
<circle cx="124.3" cy="37" r=".57" fill="#fff" stroke="#000" stroke-width=".21"/>
<circle cx="98.7" cy="31.1" r="1.04" fill="#008000" stroke="#008000" stroke-width=".21"/>
<circle cx="98.7" cy="31.1" r=".57" fill="#fff" stroke="#000" stroke-width=".21"/>
<circle cx="152.4" cy="78.5" r="1.04" fill="#008000" stroke="#008000" stroke-width=".21"/>
<circle cx="152.4" cy="78.5" r=".57" fill="#fff" stroke="#000" stroke-width=".21"/>
<circle cx="101.2" cy="74.7" r="1.04" fill="#008000" stroke="#008000" stroke-width=".21"/>
<circle cx="101.2" cy="74.7" r=".57" fill="#fff" stroke="#000" stroke-width=".21"/>
<circle cx="109.2" cy="52.9" r="1.04" fill="#008000" stroke="#008000" stroke-width=".21"/>
<circle cx="109.2" cy="52.9" r=".57" fill="#fff" stroke="#000" stroke-width=".21"/>
<circle cx="124.7" cy="58.8" r="1.04" fill="#008000" stroke="#008000" stroke-width=".21"/>
<circle cx="124.7" cy="58.8" r=".57" fill="#fff" stroke="#000" stroke-width=".21"/>
<circle cx="81.1" cy="31.5" r="1.04" fill="#008000" stroke="#008000" stroke-width=".21"/>
<circle cx="81.1" cy="31.5" r=".57" fill="#fff" stroke="#000" stroke-width=".21"/>
<circle cx="85.7" cy="65.9" r="1.04" fill="#008000" stroke="#008000" stroke-width=".21"/>
<circle cx="85.7" cy="65.9" r=".57" fill="#fff" stroke="#000" stroke-width=".21"/>
<circle cx="80.7" cy="46.6" r="1.04" fill="#008000" stroke="#008000" stroke-width=".21"/>
<circle cx="80.7" cy="46.6" r=".57" fill="#fff" stroke="#000" stroke-width=".21"/>
<circle cx="100.8" cy="26.5" r="1.04" fill="#008000" stroke="#008000" stroke-width=".21"/>
<circle cx="100.8" cy="26.5" r=".57" fill="#fff" stroke="#000" stroke-width=".21"/>
<circle cx="137.7" cy="32" r="1.04" fill="#008000" stroke="#008000" stroke-width=".21"/>
<circle cx="137.7" cy="32" r=".57" fill="#fff" stroke="#000" stroke-width=".21"/>
<circle cx="164.1" cy="94.8" r="1.04" fill="#008000" stroke="#008000" stroke-width=".21"/>
<circle cx="164.1" cy="94.8" r=".57" fill="#fff" stroke="#000" stroke-width=".21"/>
<circle cx="88.7" cy="72.2" r="1.04" fill="#008000" stroke="#008000" stroke-width=".21"/>
<circle cx="88.7" cy="72.2" r=".57" fill="#fff" stroke="#000" stroke-width=".21"/>
<circle cx="82.4" cy="62.5" r="1.04" fill="#008000" stroke="#008000" stroke-width=".21"/>
<circle cx="82.4" cy="62.5" r=".57" fill="#fff" stroke="#000" stroke-width=".21"/>
<g fill="#800000" stroke="#800000" stroke-width=".21">
<path d="M147.6 62.2h.1v14.9z"/>
<path d="M147.6 62.2l6 .1z"/>
<path d="M153.4 62.2h.2l-.1 14.9z"/>
<path d="M147.6 77l6 .1z"/>
<path d="M148.9 115.5h.1v15z"/>
<path d="M143 130.4h6z"/>
<path d="M143 115.5h.1v15z"/>
<path d="M143 115.5l6 .1z"/>
</g>
<g fill="#808000" stroke="#808000" stroke-width=".21">
<path d="M84.2 48.5l-.1 .2z"/>
<path d="M84.2 48.4l.1 .2z"/>
<path d="M84.1 48.3l.2 .1z"/>
<path d="M83.5 48.3h.7z"/>
<path d="M83.5 48.2l.1 .3z"/>
<path d="M83.5 47.7l.3 .3z"/>
<path d="M83.5 47.7h.8z"/>
<path d="M84.2 47.5l.1 .5z"/>
</g>
<g fill="#808080" stroke="#808080" stroke-width=".21">
<path d="M152.2 154.8l.8-.4h.1v.3a1.05 1.05 0 0 0-1 1 1.05 1.05 0 0 0 1 1.1v.3a1.35 1.35 0 0 1-1.2-.9 1.35 1.35 0 0 1 .3-1.4z" fill-rule="evenodd"/>
<circle cx="145.4" cy="138.6" r="3.2"/>
<circle cx="43.4" cy="42.7" r="3.2"/>
<circle cx="72.8" cy="58.6" r="2.27"/>
<circle cx="95.7" cy="58.6" r="2.27"/>
<circle cx="71.1" cy="113.1" r="5.1"/>
<circle cx="32.5" cy="27.9" r="2.62"/>
<circle cx="159.7" cy="104.7" r="2.96"/>
<circle cx="152.1" cy="104.7" r="2.96"/>
<circle cx="159.7" cy="97.1" r="2.96"/>
<circle cx="152.1" cy="97.1" r="2.96"/>
<circle cx="159.7" cy="89.5" r="2.96"/>
<circle cx="152.1" cy="89.5" r="2.96"/>
</g>
<g fill="#808080" stroke="#808080" stroke-width=".21">
<path d="M35 148.1a2.84 2.84 0 0 1 3-.8 2.84 2.84 0 0 1 2 2.5v5.8a2.85 2.85 0 0 1-2.8 2.6 2.85 2.85 0 0 1-2.9-2.6v-5.8l.2-.9z"/>
<path d="M50 148.1a2.84 2.84 0 0 1 3.1-.8 2.84 2.84 0 0 1 1.9 2.5v5.8a2.85 2.85 0 0 1-2.8 2.6 2.85 2.85 0 0 1-2.9-2.6v-5.8l.3-.9z"/>
<path d="M22.8 88.9a2.14 2.14 0 0 1 1.4-.8h4.4a2.13 2.13 0 0 1 1.9 2.1 2.13 2.13 0 0 1-1.9 2.1h-4.4a2.13 2.13 0 0 1-1.4-3.4z"/>
<path d="M22.8 96.5a2.14 2.14 0 0 1 1.4-.8h4.4a2.13 2.13 0 0 1 1.9 2.1 2.13 2.13 0 0 1-1.9 2.1h-4.4a2.13 2.13 0 0 1-1.4-3.4z"/>
<path d="M45.6 126.9a2.14 2.14 0 0 1 1.5-.7h4.3a2.13 2.13 0 0 1 1.9 2.1 2.13 2.13 0 0 1-1.9 2.1h-4.3a2.13 2.13 0 0 1-1.5-3.5z"/>
<path d="M45.6 88.9a2.14 2.14 0 0 1 1.5-.8h4.3a2.13 2.13 0 0 1 1.9 2.1 2.13 2.13 0 0 1-1.9 2.1h-4.3a2.13 2.13 0 0 1-1.5-3.4z"/>
<path d="M45.6 96.5a2.14 2.14 0 0 1 1.5-.8h4.3a2.13 2.13 0 0 1 1.9 2.1 2.13 2.13 0 0 1-1.9 2.1h-4.3a2.13 2.13 0 0 1-1.5-3.4z"/>
<path d="M76.9 64.2a2.45 2.45 0 0 1 2.6-.7 2.45 2.45 0 0 1 1.7 2.1v5a2.44 2.44 0 0 1-2.5 2.2 2.44 2.44 0 0 1-2.4-2.2v-5l.2-.7z"/>
<path d="M69.3 64.2a2.45 2.45 0 0 1 2.6-.7 2.45 2.45 0 0 1 1.7 2.1v5a2.44 2.44 0 0 1-2.5 2.2 2.44 2.44 0 0 1-2.4-2.2v-5l.2-.7z"/>
<path d="M61.6 64.2a2.45 2.45 0 0 1 2.7-.7 2.45 2.45 0 0 1 1.6 2.1v5a2.44 2.44 0 0 1-2.4 2.2 2.44 2.44 0 0 1-2.4-2.2v-5l.1-.7z"/>
<path d="M22.3 25.3h5.2v5.2h-5.2z"/>
<path d="M158.6 71.1l.9-.7 .8-.1h4.9a2.44 2.44 0 0 1 2.3 2.4 2.44 2.44 0 0 1-2.3 2.4h-4.9a2.44 2.44 0 0 1-2.1-1.5 2.44 2.44 0 0 1 .4-2.5z"/>
<path d="M158.6 63.5l.9-.7 .8-.2h4.9a2.44 2.44 0 0 1 2.3 2.5 2.44 2.44 0 0 1-2.3 2.4h-4.9a2.44 2.44 0 0 1-2.1-1.5 2.44 2.44 0 0 1 .4-2.5z"/>
<path d="M158.6 55.9l.9-.7 .8-.2h4.9a2.44 2.44 0 0 1 2.3 2.4 2.44 2.44 0 0 1-2.3 2.5h-4.9a2.44 2.44 0 0 1-2.1-1.5 2.44 2.44 0 0 1 .4-2.5z"/>
<path d="M158.6 48.2l.9-.6 .8-.2h4.9a2.44 2.44 0 0 1 2.3 2.4 2.44 2.44 0 0 1-2.3 2.5h-4.9a2.44 2.44 0 0 1-2.1-1.5 2.44 2.44 0 0 1 .4-2.6z"/>
<path d="M158.6 40.6l.9-.7 .8-.1h4.9a2.44 2.44 0 0 1 2.3 2.4 2.44 2.44 0 0 1-2.3 2.4h-4.9a2.44 2.44 0 0 1-2.1-1.5 2.44 2.44 0 0 1 .4-2.5z"/>
<path d="M158.6 33l.9-.7 .8-.1h4.9a2.44 2.44 0 0 1 2.3 2.4 2.44 2.44 0 0 1-2.3 2.4h-4.9a2.44 2.44 0 0 1-2.1-1.5 2.44 2.44 0 0 1 .4-2.5z"/>
<path d="M102.6 91.6h6.1v6.1h-6.1z"/>
<path d="M119.5 49.3h1.9v6.3h-1.9z"/>
<path d="M123.3 49.3h1.9v6.3h-1.9z"/>
<path d="M127.1 49.3h1.9v6.3h-1.9z"/>
<path d="M130.9 49.3h1.9v6.3h-1.9z"/>
<path d="M134.7 49.3h2v6.3h-2z"/>
<path d="M138.6 49.3h1.9v6.3h-1.9z"/>
<path d="M142.4 49.3h1.9v6.3h-1.9z"/>
<path d="M146.2 49.3h1.9v6.3h-1.9z"/>
<path d="M146.2 21.2h1.9v6.3h-1.9z"/>
<path d="M142.4 21.2h1.9v6.3h-1.9z"/>
<path d="M138.6 21.2h1.9v6.3h-1.9z"/>
<path d="M134.7 21.2h2v6.3h-2z"/>
<path d="M130.9 21.2h1.9v6.3h-1.9z"/>
<path d="M127.1 21.2h1.9v6.3h-1.9z"/>
<path d="M123.3 21.2h1.9v6.3h-1.9z"/>
<path d="M119.5 21.2h1.9v6.3h-1.9z"/>
<path d="M147.7 62.8h5.7v5.1h-5.7z"/>
<path d="M147.7 71.3h5.7v5.2h-5.7z"/>
<path d="M151.1 153.3h4.8v4.8h-4.8z"/>
<path d="M140.6 153.3h4.8v4.8h-4.8z"/>
<path d="M157.9 117.5h5.1v7.2h-5.1z"/>
<path d="M157.9 136.4h5.1v7.2h-5.1z"/>
<path d="M143.1 124.7h5.7v5.1h-5.7z"/>
<path d="M143.1 116.1h5.7v5.2h-5.7z"/>
<path d="M40 24.4a2.14 2.14 0 0 1 2.3-.7 2.14 2.14 0 0 1 1.5 1.8v4.4a2.15 2.15 0 0 1-2.2 2 2.15 2.15 0 0 1-2.1-2v-4.4z"/>
<path d="M55.2 24.4a2.14 2.14 0 0 1 2.3-.7 2.14 2.14 0 0 1 1.5 1.8v4.4a2.15 2.15 0 0 1-2.1 2 2.15 2.15 0 0 1-2.2-2v-4.4z"/>
<path d="M47.6 24.4a2.14 2.14 0 0 1 2.3-.7 2.14 2.14 0 0 1 1.5 1.8v4.4a2.15 2.15 0 0 1-2.1 2 2.15 2.15 0 0 1-2.2-2v-4.4z"/>
<path d="M132.5 99.1l.6-.3 .7-.2h4.6a2.29 2.29 0 0 1 2.1 2.3 2.29 2.29 0 0 1-2.1 2.3h-4.6a2.29 2.29 0 0 1-2-1.6 2.29 2.29 0 0 1 .7-2.5z"/>
<path d="M132.5 91.5l.6-.4 .7-.1h4.6a2.29 2.29 0 0 1 2.1 2.3 2.29 2.29 0 0 1-2.1 2.2h-4.6a2.29 2.29 0 0 1-2-1.5 2.29 2.29 0 0 1 .7-2.5z"/>
<path d="M36.5 78l1.1-.9 1.3-.3h7a3.4 3.4 0 0 1 3.2 3.4 3.4 3.4 0 0 1-3.2 3.5h-7a3.4 3.4 0 0 1-3-2.2 3.4 3.4 0 0 1 .6-3.5z"/>
<path d="M30.8 60.3a3.4 3.4 0 0 1 3.7-1 3.4 3.4 0 0 1 2.3 3v7a3.4 3.4 0 0 1-3.4 3.2 3.4 3.4 0 0 1-3.4-3.2v-7l.3-1.3z"/>
<path d="M48.8 60.3a3.4 3.4 0 0 1 3.7-1 3.4 3.4 0 0 1 2.3 3v7a3.4 3.4 0 0 1-3.4 3.2 3.4 3.4 0 0 1-3.4-3.2v-7l.3-1.3z"/>
<path d="M113.1 108h7.9v4.1h-7.9z"/>
<path d="M113.1 115.6h7.9v4.1h-7.9z"/>
<path d="M90.2 108h7.9v4.1h-7.9z"/>
<path d="M90.2 115.6h7.9v4.1h-7.9z"/>
<path d="M119.7 49.5h1.6v5.9h-1.6z"/>
<path d="M123.5 49.5h1.6v5.9h-1.6z"/>
<path d="M127.3 49.5h1.6v5.9h-1.6z"/>
<path d="M131.1 49.5h1.6v5.9h-1.6z"/>
<path d="M134.9 49.5h1.6v5.9h-1.6z"/>
<path d="M138.7 49.5h1.6v5.9h-1.6z"/>
<path d="M142.5 49.5h1.6v5.9h-1.6z"/>
<path d="M146.3 49.5h1.6v5.9h-1.6z"/>
<path d="M146.3 21.4h1.6v5.9h-1.6z"/>
<path d="M142.5 21.4h1.6v5.9h-1.6z"/>
<path d="M138.7 21.4h1.6v5.9h-1.6z"/>
<path d="M134.9 21.4h1.6v5.9h-1.6z"/>
<path d="M131.1 21.4h1.6v5.9h-1.6z"/>
<path d="M127.3 21.4h1.6v5.9h-1.6z"/>
<path d="M123.5 21.4h1.6v5.9h-1.6z"/>
<path d="M119.7 21.4h1.6v5.9h-1.6z"/>
<path d="M147.8 63h5.5v4.8h-5.5z"/>
<path d="M147.8 71.5h5.5v4.8h-5.5z"/>
<path d="M151.3 153.5h4.5v4.5h-4.5z"/>
<path d="M140.8 153.5h4.5v4.5h-4.5z"/>
<path d="M158.1 117.7h4.8v6.9h-4.8z"/>
<path d="M158.1 136.6h4.8v6.9h-4.8z"/>
<path d="M143.3 124.8h5.4v4.8h-5.4z"/>
<path d="M143.3 116.3h5.4v4.8h-5.4z"/>
<path d="M113.2 108.1h7.7v3.8h-7.7z"/>
<path d="M113.2 115.7h7.7v3.8h-7.7z"/>
<path d="M90.4 108.1h7.6v3.8h-7.6z"/>
<path d="M90.4 115.7h7.6v3.8h-7.6z"/>
<path d="M148.5 68.7h4.2v1.8h-4.2z"/>
<path d="M143.9 122h4.2v1.9h-4.2z"/>
<path d="M61.6 68.1h3.8v5h-3.8z"/>
<path d="M69.2 68.1h3.8v5h-3.8z"/>
<path d="M76.8 68.1h3.8v5h-3.8z"/>
<path d="M56.1 37h2.3v1.1h-2.3z"/>
<path d="M56.1 51.1h2.3v1.1h-2.3z"/>
<path d="M162 41.4h1.5v1.6h-1.5z"/>
<path d="M162 49.1h1.5v1.5h-1.5z"/>
<path d="M162 56.7h1.5v1.5h-1.5z"/>
<path d="M162 64.3h1.5v1.5h-1.5z"/>
<path d="M162 71.9h1.5v1.5h-1.5z"/>
<path d="M162 33.8h1.5v1.5h-1.5z"/>
<path d="M147.9 72.5h5.3v2.2h-5.3z"/>
<path d="M147.9 64.6h5.3v2.2h-5.3z"/>
<path d="M152.8 153.2h.4v1.5h-.4z"/>
<path d="M152 153.2h.9v.7h-.9z"/>
<path d="M152 154.4h.6v.3h-.6z"/>
<path d="M152 153.8h.3v1.2h-.3z"/>
<path d="M152.2 156.8h1v1.5h-1z"/>
<path d="M152 156.5h.3v1.8h-.3z"/>
<path d="M151.1 153.2h.9v5.1h-.9z"/>
<path d="M143.3 153.2h2.1v5.1h-2.1z"/>
<path d="M158.9 103.9h1.6v1.6h-1.6z"/>
<path d="M151.3 103.9h1.5v1.6h-1.5z"/>
<path d="M151.3 96.3h1.5v1.5h-1.5z"/>
<path d="M158.9 96.3h1.6v1.5h-1.6z"/>
<path d="M151.3 88.7h1.5v1.5h-1.5z"/>
<path d="M158.9 88.7h1.6v1.5h-1.6z"/>
<path d="M143.4 117.9h5.2v2.2h-5.2z"/>
<path d="M143.4 125.8h5.2v2.2h-5.2z"/>
<path d="M109.1 44.9h2.2v1.1h-2.2z"/>
<path d="M109.1 30.8h2.2v1.1h-2.2z"/>
<path d="M135.2 92.4h1.8v1.8h-1.8z"/>
<path d="M135.2 100h1.8v1.8h-1.8z"/>
<path d="M38.7 79.5h7.4v1.5h-7.4z"/>
<path d="M50.7 61.3h1.4v9h-1.4z"/>
<path d="M33.1 62.1h.6v7.5h-.6z"/>
<circle cx="142.1" cy="82.5" r="2.32"/>
<circle cx="111.6" cy="82.5" r="2.32"/>
<circle cx="57.2" cy="52.2" r="2.32"/>
<circle cx="57.2" cy="37" r="2.32"/>
<circle cx="105.6" cy="154.7" r="3.3"/>
<circle cx="110.2" cy="30.8" r="2.32"/>
<circle cx="110.2" cy="46" r="2.32"/>
<circle cx="142.2" cy="71.9" r="2.32"/>
<circle cx="104.1" cy="71.9" r="2.32"/>
</g>
<g fill="none" stroke="#7f7f7f" stroke-width=".21">
<path d="M142.7 19.9h1.2v.7h-1.2zM142.7 20h1.2M142.7 19.9h1.2M142.7 20.6h1.2M142.7 20.5h1.2M142.7 20.4h1.2M142.7 20.3h1.2M142.7 20.2h1.2M142.7 20.1h1.2M153.7 33.6v1.1l.5 .6 .6-.6v-1.1M156.5 33.9l-.3-.3h-.6l-.2 .3v1.1l.2 .3h.6l.3-.3M158.2 33.9l-.3-.3h-.6l-.2 .3v1.1l.2 .3h.6l.3-.3"/>
<path d="M154.8 41.5l-.3-.3h-.5l-.3 .3v1.1l.3 .3h.5l.3-.3v-.5h-.6M155.1 49.3l-.3-.3h-.5l-.3 .3v.2l.3 .3h.5l.3 .3v.3l-.3 .3h-.5l-.3-.3M155.1 56.9l-.3-.3h-.5l-.3 .3v.3l.3 .2h.5l.3 .3v.3l-.3 .3h-.5l-.3-.3M155.7 49h.8l.3 .3v1.1l-.3 .3h-.8zM156.5 41.2v1.7l-1.1-1.7v1.7M156.8 56.9l-.3-.3h-.5l-.3 .3v1.1l.3 .3h.5l.3-.3M157.1 41.2h.8l.3 .3v1.1l-.3 .3h-.8zM157.4 49.8h1.1M157.4 50.7v-1.2l.5-.5 .6 .5v1.2M157.4 56.6v1.7h1.1M57.4 77.6h27.4v24.8h-27.4zM155.2 65.2h.8l.3-.3v-.6l-.3-.2h-.8v1.6"/>
<path d="M155.2 71.7h1.1M155.8 65.2l.5 .5M155.8 71.7v1.7M156.9 64.1l1.1 1.6M156.9 71.7l1.1 1.7M158 64.1l-1.1 1.6M158 71.7l-1.1 1.7M143.1 94.4v.6M143.1 97.5l.3-.3h1.1l.3 .3v.6l-.3 .2h-1.1l-.3-.2zM143.1 94.7h1.7M143.1 88.9h1.7l-1.7 1.1h1.7M143.4 87.2h1.1l.3 .2v.9h-1.7v-.9z"/>
<path d="M143.4 90.5l-.3 .3v.6l.3 .3h1.1l.3-.3v-.6l-.3-.3h-.5v.6M143.4 95.5l-.3 .3v.6l.3 .3h.3l.3-.3v-.6l.3-.3h.2l.3 .3v.6l-.3 .3M144.8 98.9h-1.7l.6 .6-.6 .5h1.7M144.8 94.4v.6M163.7 95.9h1.7M163.7 94.8l1.1 1.1M164 98.1l-.3 .3v.6l.3 .3h.3l.2-.3v-.6l.3-.3h.3l.3 .3v.6l-.3 .3M164 96.5l-.3 .3v.5l.3 .3h1.1l.3-.3v-.5l-.3-.3M165.4 94.8l-.9 .8M166.8 86.7v1.1h1.6v-1.1M166.8 90.1v1.1h1.6v-1.1M166.8 85v1.1"/>
<path d="M166.8 85.6h1.6M167 88.4l-.2 .3v.5l.2 .3h.3l.3-.3v-.5l.3-.3h.2l.3 .3v.5l-.3 .3M167.6 87.3v.5M167.6 90.6v.6M167.9 92.9v-.9l-.3-.2h-.6l-.2 .2v.9h1.6M168.4 91.8l-.5 .5M143.1 106.5h1.2l.5 .6-.5 .6h-1.2M143.4 103.2l-.3 .2v.6l.3 .3h1.1l.3-.3v-.6l-.3-.2M143.4 104.9l-.3 .2v.6l.3 .3h1.1l.3-.3v-.6l-.3-.2M166.8 102.3l.2-.3h1.1l.3 .3v.6l-.3 .3h-1.1l-.2-.3zM166.8 105.7h1.6M166.8 105.4v.6"/>
<path d="M167 103.7l-.2 .3v.6l.2 .2h.3l.3-.2v-.6l.3-.3h.2l.3 .3v.6l-.3 .2M168.4 106.5h-1.6l.5 .6-.5 .6h1.6M168.4 105.4v.6"/>
</g>
<g fill="none" stroke="#7f7f7f" stroke-width=".23">
<path d="M35.9 17.8l-.5-.4h-.9l-.5 .4v1.9l.5 .5h.9l.5-.5M36.8 18.3l1-.9v2.8M36.8 20.2h1.9M45.9 33.2h1.9M46.8 33.2v2.8M48.7 34.2l.9-1v2.8M48.7 36h1.9M103.9 38.7l-.5 .5v.9l.5 .5h1.9l.5-.5v-.9l-.5-.5M104.9 36.4l-.5-.5h-.5l-.5 .5v.9l.5 .5M104.9 36.4l.4-.5h.5l.5 .5v.9l-.5 .5M104.9 36.4v.4M62.6 55.2l-.5 .5v.9l.5 .5h1.9l.4-.5v-.9l-.4-.5"/>
<path d="M62.6 58l-.5 .5v.9l.5 .5h1.9l.4-.5v-.9l-.4-.5M67.4 58h2.9l-2.9 1.9h2.9M67.9 55.2h1.9l.5 .5v1.4h-2.9v-1.4zM78.3 58.5l.7-.7v2.2M82 57.8v2.2l-1.5-2.2v2.2M84.2 58.9h-1.5l1.2-1.1v2.2M85 58.5l.7-.7v2.2M88.7 58.9h-1.5l1.1-1.1v2.2M89.9 58.9l-.4 .4v.3l.4 .4h.7l.4-.4v-.3l-.4-.4M89.9 58.9h.7M89.9 58.9l-.4-.4v-.3l.4-.4h.7l.4 .4v.3l-.4 .4M116.2 52.4l2.3 2.4"/>
<path d="M116.2 53.6h2.3M117.3 52.4v2.4M118.5 52.4l-2.3 2.4M30.2 62.7l-.4-.5h-1l-.5 .5v1.8l.5 .5h1l.4-.5M31.2 62.7l.4-.5h1l.4 .5v.4l-1.8 1.9h1.8M38.3 65.3h2.8l-2.8 1.9h2.8M38.8 68.1l-.5 .5v.9l.5 .5h1.9l.4-.5v-.9l-.4-.5h-1v.9M38.8 62.5h1.9l.4 .5v1.4h-2.8v-1.4zM55.3 67.3h1.9l.9 1-.9 .9h-1.9M55.3 66h2.8M55.3 65.5v.9M55.3 62.7h2.8l-2.8 1.8h2.8"/>
<path d="M58.1 65.5v.9M62.1 60.8h1.9l.9 1-.9 .9h-1.9M67.9 60.8l-.5 .5v.9l.5 .5h1.9l.5-.5v-.9l-.5-.5h-1v1M78.3 60h1.4M82.7 69.8h1.8l1 .9-1 1h-1.8M82.7 68.4h2.8M82.7 67.9v1M82.7 65.1h2.8l-2.8 1.9h2.8M85 60h1.5M85.5 67.9v1M99.6 76.9v-1.9h.5l1.9 1.9h.4M101.5 79.7v-1.4l-.5-.5h-.9l-.5 .5v1.4h2.8"/>
<path d="M102.4 77.8l-.9 1M121 72.4h1.4l.5-.5v-.9l-.5-.5h-1.4v2.8M121.9 72.4l1 .9M123.8 71l.4-.5h1l.4 .5v.5l-1.8 1.8h1.8M124.5 83.1h1.4l.5-.5v-1l-.5-.4h-1.4v2.8M125.4 83.1l1 .9M127.3 82.1l.9-.9v2.8M127.3 84h1.9M135.4 111.7h1.9M136.4 111.7v2.8M138.2 111.7h1M138.2 114.5h1"/>
<path d="M138.7 111.7v2.8M139.9 118.6l-.5-.4h-.4l-.5 .4v1l.5 .4h.4l.5-.4M139.9 118.6l.5-.4h.4l.5 .4v1l-.5 .4h-.4l-.5-.4M139.9 118.6v1M140.1 114.5v-2.8l1 .9 .9-.9v2.8M142.9 113.1h1M144.8 111.7h-1.9v2.8h1.9M148.5 114.5v-2.8l1 .9 .9-.9v2.8M151.8 111.7h1l.4 .4v1.9l-.4 .5h-1l-.5-.5v-1.9zM154.1 111.7h1.5l.4 .4v1.9l-.4 .5h-1.5zM157 113.1h.9M158.8 111.7h-1.8v2.8h1.8"/>
<path d="M164.4 112.1l-.4-.4h-1l-.4 .4v.5l.4 .5h1l.4 .4v.5l-.4 .5h-1l-.4-.5M165.4 111.7v2.8l.9-1 1 1v-2.8M140.4 122.9v-1.5l-.5-.4h-.9l-.5 .4v1.5h2.8M141.3 121l-.9 .9M135.7 145.9h1.9M136.2 150.5h1l.4 .5v1.9l-.4 .4h-1l-.5-.4v-1.9zM136.7 145.9v2.9M138.6 145.9h.9M138.6 148.8h.9M139 145.9v2.9M140.4 148.8v-2.9l1 1 .9-1v2.9M140.4 150.5v2.8l-1.8-2.8v2.8"/>
<path d="M141.7 159.9v.5M143.2 147.3h1M145.1 145.9h-1.9v2.9h1.9M148.8 148.8v-2.9l1 1 .9-1v2.9M152.1 145.9h1l.4 .5v1.9l-.4 .5h-1l-.5-.5v-1.9zM154.5 145.9h1.4l.4 .5v1.9l-.4 .5h-1.4zM157.2 147.3h1M159.1 145.9h-1.9v2.9h1.9M126.3 162.3h1.4l.5-.5v-.9l-.5-.5h-1.4v2.8M129.1 160.4h.5v2.8M129.1 163.2h.9M131.4 161.4h1l.5 .4v1.4h-1.5l-.4-.4 .4-.5h1.5"/>
<path d="M133.8 163.2v-1.8h1.4l.5 .4v1.4M136.6 161.4h.9M137.1 160.9v1.9l.4 .4M138.5 160.4v2.8h1.8M141.3 163.2h.9M141.3 161.4h.4v1.8M145 163.2h-1.4l-.5-.4v-1l.5-.4h1.4v2.3l-.5 .5h-.4M145.9 161.8l.5-.4h.9l.5 .4v1.4M145.9 160.4v2.8M148.7 161.4h1M149.2 160.9v1.9l.5 .4M153.4 161.4l1 1.8 .9-1.8"/>
<path d="M156.2 160.9l.5-.5h.9l.5 .5v.5l-.5 .4M157.2 161.8h.4M157.6 161.8l.5 .5v.5l-.5 .4h-.9l-.5-.4M159 162.8h.5v.4h-.5zM162.3 160.9l-.5-.5h-.9l-.5 .5v1.9M162.3 160.9v1.9l-.5 .4h-.9l-.5-.4M162.3 160.9l-1.9 1.9"/>
</g>
<g fill="none" stroke="#7f7f7f" stroke-width=".47">
<path d="M160.4 18.6h.8l.9 .9 .9-.9h.9l.9 .9v2.7h-5.3v-2.7zM162.1 19.5v2.7M53.8 39.7v9.9M60.6 39.7v9.9M106.8 33.4v9.9M110.2 34.6v2.9M110.2 39.4v2.8M113.6 33.4v9.9M118.6 26.7h-1v23.4h1M149 26.7h.9v23.4h-.9M160.4 23.9l-.9 .9v1.8l.9 .9h3.5l.9-.9v-1.8l-.9-.9h-1.8v1.8M160.8 38.4l-1.9-1.9v-3.8l1.9-1.9h3.9l1.9 1.9v3.8l-1.9 1.9"/>
<path d="M160.8 38.4l-1.9 1.9v3.8l1.9 1.9M160.8 38.4h3.9M164.7 38.4l1.9 1.9v3.8l-1.9 1.9M57.2 40.8v2.8M57.2 45.5v2.9M160.8 46l-1.9 1.9v3.8l1.9 1.9M160.8 53.6l-1.9 1.9v3.9l1.9 1.9M160.8 46h3.9M160.8 53.6h3.9M164.7 46l1.9 1.9v3.8l-1.9 1.9M164.7 53.6l1.9 1.9v3.9l-1.9 1.9M55.5 75.7h31.2v37.4h-2.6v4.5h2.6v5.7h-31.2v-5.7h2.7v-4.5h-2.7z"/>
<path d="M110.3 67.7l.7-.3h1.9l.3 .3h19.8l.4-.3h2.2l.3 .3 .2 .4v7.9l-.3 .3-.5 .2h-1.9l-.4-.4h-19.8l-.3 .4h-2.2l-.4-.3-.1-.5v-7.6zM117.5 79.4l.6-.4h1.2l.3 .4h14.5l.4-.4 1.4 .1 .3 .3 .2 .4v5.6l-.3 .3-.5 .2h-1.1l-.4-.4h-14.5l-.3 .4h-1.4l-.4-.3-.2-.5v-5.3zM160.8 61.3l-1.9 1.9v3.8l1.9 1.9M160.8 68.9l-1.9 1.9v3.8l1.9 1.9h3.9l1.9-1.9v-3.8l-1.9-1.9M160.8 68.9h3.9M160.8 61.3h3.9M164.7 61.3l1.9 1.9v3.8l-1.9 1.9M132.3 90.2l.7-.7h6.1l.8 .7v6.1l-.8 .8 .8 .7v6.1l-.8 .8h-6.1l-.7-.8v-6.1l.7-.7-.7-.8zM96.9 106.2h5.7a3 3 0 0 0 3 3.1 3 3 0 0 0 3.1-3.1h5.7v15.2h-17.5zM29.7 137.7h29.9v27.5h-29.9zM29.7 138.3h29.9M29.7 158.1h4.8"/>
<path d="M39.8 158.1h9.7M54.8 158.1h4.8"/>
<circle cx="71.1" cy="113.1" r="5.4"/>
<circle cx="37.2" cy="142.2" r="1.52"/>
<circle cx="52.2" cy="142.2" r="1.52"/>
</g>
<path d="M107.9 37.5h4.6M107.9 39.4h4.6M54.9 45.5h4.6M54.9 43.6h4.6M146 84.1h19.8v25.9h-19.8z" fill="none" stroke="#7f7f7f" stroke-width=".93"/>
<g fill="#7f7f7f" stroke="#7f7f7f" stroke-width=".21">
<path d="M165.8 94h2.3v6.1h-2.3z"/>
<path d="M114.8 81.6h2.5v1.8h-2.5z"/>
<path d="M136.4 81.6h2.6v1.8h-2.6z"/>
<path d="M61.6 73.1h3.8v2.6h-3.8z"/>
<path d="M69.2 73.1h3.8v2.6h-3.8z"/>
<path d="M76.8 73.1h3.8v2.6h-3.8z"/>
<path d="M149.3 153.2h1.3v1h-1.3z"/>
<path d="M149.3 157.3h1.3v1h-1.3z"/>
<path d="M148.3 155.2h1v1.1h-1z"/>
<path d="M107.6 71h2.6v1.8h-2.6z"/>
<path d="M136.1 71h2.6v1.8h-2.6z"/>
</g>
<g fill="none" stroke="#7f7f7f" stroke-width=".61">
<path d="M31 32.1h3M75.9 58.6h.7M76.6 56.3h15.3v4.6h-15.3zM90 56.7v3.8M91.9 58.6h.7M150.2 93.3l-1.9-1.9v-3.9l1.9-1.9h11.4l1.9 1.9v3.9l-1.9 1.9M150.2 93.3l-1.9 1.9v3.8l1.9 1.9M150.2 93.3h11.4M161.6 93.3l1.9 1.9v3.8l-1.9 1.9M150.2 100.9l-1.9 1.9v3.8l1.9 1.9h11.4l1.9-1.9v-3.8l-1.9-1.9M150.2 100.9h11.4M164.5 102.8v3.8"/>
<path d="M157.2 121.6h-1.5l-.3 .3-.2 .4v16.5l.2 .5 .3 .3h1.5M158.2 126.1h4.5v9h-4.5zM163.8 121.6h1.4l.4 .3 .1 .4v16.5l-.1 .5-.4 .3h-1.4"/>
<circle cx="28.7" cy="27.9" r="7.5"/>
</g>
<g fill="none" stroke="#7f7f7f" stroke-width=".38">
<path d="M42 24.3a8 8 0 0 1 7.2-4.6 8 8 0 0 1 7.3 4.6M45 28.1h.8M52.7 28.1h.8M56.5 31.1l-1 1.6h-12.5l-1-1.6M22.8 86.8h30v44.9h-30zM31.2 97.8h2.8v14.3h1M31.2 90.2h6.6v21.9h-.9l-1 1.9v14.3h8.6M39.7 93.1h3.8v1.9h-3.8zM41.6 95v2.8h2.9M44.5 90.2h-2.9v2.9M31.3 144.5l1.1-1.2v3.5M31.3 146.8h2.3"/>
<path d="M46.1 143.9l.6-.6h1.1l.6 .6v.6l-2.3 2.3h2.3"/>
</g>
<g fill="none" stroke="#7f7f7f" stroke-width=".32">
<path d="M10.2 56.2h2.9M16.2 56.2h3M20.6 52.3v27M20.6 53.8h31.5v5M22.1 56.2h3M28.2 56.2h2.9M34.1 56.2h3v4.4M50.6 53.8v5M10.2 75.4h2.9M16.2 62.8a3 3 0 0 0-3.1 3 3 3 0 0 0 3.1 3M16.2 75.4h3M22.1 75.4h3"/>
<path d="M28.2 75.4h2.9M37.1 71v4.4h-3M37.1 63.6v4.4M46.1 74v-21.7h-35.9v27h24.5M50.6 72.9v4.9h1.5v-4.9M66.4 106v-1.8l.9-.9 .9 .9v1.8M66.4 104.6h1.8M69.1 104.2l.9-.9v2.7M69.1 106h1.8M73.6 103.3h-1.8v1.3l.9-.4h.5l.4 .4v.9l-.4 .5h-.9l-.5-.5M75 105.5h.5v.5h-.5zM75.5 106l-.9 .9"/>
<path d="M76.4 103.8l.5-.5h.8l.5 .5v.4l-1.8 1.8h1.8M80 104.6l-.4-.4h-.5v1.8M80 104.6v1.4M80 104.6l.5-.4 .4 .4v1.4M82.8 104.6l-.5-.4h-.4v1.8M82.8 104.6v1.4M82.8 104.6l.4-.4 .5 .4v1.4"/>
</g>
<g fill="#7f7f7f" stroke="#7f7f7f" stroke-width=".21">
<path d="M53.6 49.6h.4l.3 .8 .4 .3 .6 .2v.4a1.71 1.71 0 0 1-1.7-1.7z" fill-rule="evenodd"/>
<path d="M60.4 49.6h.5a1.75 1.75 0 0 1-1.8 1.7v-.4l.6-.2 .4-.3z" fill-rule="evenodd"/>
<path d="M54.2 38.3l1.1-.4v.5l-.6 .1-.4 .3-.3 .9h-.4v-.6z" fill-rule="evenodd"/>
<path d="M59.1 37.9a1.71 1.71 0 0 1 1.8 1.8h-.5l-.3-.9-.4-.3-.6-.1z" fill-rule="evenodd"/>
<path d="M112.1 31.7a1.75 1.75 0 0 1 1.7 1.7h-.4l-.3-.8-.5-.3-.5-.1z" fill-rule="evenodd"/>
<path d="M106.9 32.3l.6-.4 .8-.2v.5l-.6 .1-.4 .3-.3 .8h-.5z" fill-rule="evenodd"/>
<path d="M112.1 44.6l.5-.1 .5-.3 .3-.9h.4a1.71 1.71 0 0 1-1.7 1.8z" fill-rule="evenodd"/>
<path d="M106.5 43.3h.5l.3 .9 .4 .3 .6 .1v.5a1.75 1.75 0 0 1-1.8-1.8z" fill-rule="evenodd"/>
</g>
<path d="M104.1 71.9h3.8M138.4 71.9h3.8M111.6 82.5h3.1M139.1 82.5h3" fill="none" stroke="#808080" stroke-width="1.8"/>
<path d="M40.2 149.7l-6 6M55.1 149.6l-6 6.1" fill="none" stroke="#808080" stroke-width=".76"/>
<g fill="none" stroke="#808080" stroke-width=".47">
<path d="M55.3 38.1h3.8M108.3 31.9h3.8M118 37.5a.91 .91 0 0 1 1 .9 .91 .91 0 0 1-.9 .9M118.1 27h31.4v22.8h-31.4zM119.7 22.5h1.5v4.6h-1.4zM123.5 22.5h1.5v4.6h-1.4zM127.3 22.5h1.5v4.6h-1.4zM131.1 22.5h1.5v4.6h-1.4zM134.9 22.5h1.5v4.6h-1.4zM138.7 22.5l1.5-.1v4.6l-1.4 .1zM142.6 22.5l1.4-.1v4.6l-1.4 .1zM146.4 22.5l1.4-.1v4.6l-1.3 .1z"/>
<path d="M55.3 51.1h3.8M108.3 44.9h3.8M119.8 49.8l1.4-.1v4.6l-1.4 .1zM123.6 49.8l1.4-.1 .1 4.6-1.5 .1zM127.4 49.8l1.4-.1v4.6l-1.4 .1zM131.2 49.7h1.4l.1 4.6h-1.5zM135 49.7h1.4l.1 4.6h-1.5zM138.8 49.7h1.4l.1 4.6h-1.5zM142.6 49.7h1.4l.1 4.6h-1.5zM146.5 49.7h1.3l.1 4.6h-1.4zM148.1 66.8v5.7M153 66.8v5.7"/>
<path d="M143.6 120.1v5.7M148.4 120.1v5.7M34.5 158.1h5.3M49.5 158.1h5.3"/>
<circle cx="37.2" cy="152.7" r="4.5"/>
<circle cx="52.2" cy="152.7" r="4.5"/>
</g>
<g fill="none" stroke="#808080" stroke-width=".38">
<path d="M57.8 16.5h2.3M58.9 16.5v3.4M61.3 17.6l1.2-1.1v3.4M61.3 19.9h2.3M41.3 28.1l.2 1.6 .5 1.4M41.3 28.1h3.7M42 24.3l-.5 1.5-.2 2.3M45.8 28.1h6.9M53.5 28.1h3.7M56.5 24.3l.5 1.5 .2 2.3M57.2 28.1l-.2 1.6-.5 1.4M61.6 32.8v2.3h3.4"/>
<path d="M62.7 36.3h2.3v1.7l-.5 .6h-1.8M63.3 34v1.1M102.4 33v2.2h3.4M103.5 36.5h2.3v1.7l-.6 .6h-1.7M104.1 34.1v1.1M105.8 40v2.2M115.1 36.5l-.5 .5v1.2l.5 .6h2.3l.6-.6v-1.2l-.6-.5M116.3 33.5l-.6-.5h-.6l-.5 .5v1.2l.5 .5M116.3 33.5l.6-.5h.5l.6 .5v1.2l-.6 .5M116.3 33.5v.6M50 48.6l-.6 .6v1.1l.6 .6h2.3l.5-.6v-1.1l-.5-.6M52.8 45.1v2.3l-2.3-2.3h-.5l-.6 .6v1.1l.6 .6"/>
<path d="M62.2 48.6l-.6 .6v1.1l.6 .6h2.3M62.2 48.6h2.3l.5 .6v1.1l-.5 .6M62.2 48.6l2.3 2.3M63.3 40.4l-.6-.6h-.5l-.6 .6v1.2l.6 .5M63.3 43.9l-.6-.6h-.5l-.6 .6v1.2l.6 .5M63.3 40.4l.6-.6h.6l.5 .6v1.2l-.5 .5M63.3 43.9l.6-.6h.6l.5 .6v1.2l-.5 .5M63.3 40.4v.6M63.3 43.9v.6M64.5 46.8h.5v.6h-.5zM103 45.2l-.6 .6v1.1l.6 .6h2.2M103 45.2h2.2l.6 .6v1.1l-.6 .6"/>
<path d="M103 45.2l2.2 2.3M105.2 43.4h.6v.6h-.6zM105.8 41.1h-3.4l1.1 1.1M78.1 79.7h1.2M78.7 79.7v3.5M121.9 70.2h-2.3v1.7l1.1-.5h.6l.6 .5v1.2l-.6 .5h-1.1l-.6-.5M123.1 71.9h1.7l.6 .6v.6l-.6 .5h-1.1l-.6-.5zM125.4 70.2l-1.2 .6-1.1 1.1M125.5 79h1.7l.5-.6v-1.1l-.5-.6h-1.7v3.4M126.6 79l1.1 1.1M128.9 70.8l-.6-.6h-1.1l-.6 .6v2.3M128.9 70.8v2.3l-.6 .5h-1.1l-.6-.5"/>
<path d="M128.9 70.8l-2.3 2.3M129 77.3l.5-.6h1.2l.6 .6v.5l-2.3 2.3h2.3M153.6 74.8h2.9l.6 .6v.6l-.6 .5M153.6 74.3v1.1M155.9 73v-1.7l-.5-.6h-1.2l-.6 .6v1.7h3.5M157.1 67.2v2.3M157.1 68.4h-3.5l1.2 1.1M61.7 80.3l.6-.6h1.1l.6 .6v2.3l-.6 .6h-1.1l-.6-.6zM69.3 81.4h2.3M78.1 83.2h1.2M123.1 88.8h1.7l.6-.6v-1.2l-.6-.5h-1.7v3.4M124.2 88.8l1.2 1.1"/>
<path d="M126.6 87.6l1.1-1.1v3.4M126.6 89.9h2.3M126.8 81.9l1.2-1.1v3.4M126.8 84.2h2.3M130.3 80.8v3.4M130.9 82.5l1.7 1.7M130.9 95.2v2.3l-2.2-2.3h-.6l-.6 .6v1.1l.6 .6M132.6 80.8l-2.3 2.2M153 85h.4M153 83.5h.4M153.2 83.5v1.5M155 83.8l-.2-.3h-.5l-.2 .3v1l.2 .2h.5l.2-.2"/>
<path d="M156.7 83.8l-.2-.3h-.5l-.2 .3v.2l.2 .3h.5l.2 .2v.3l-.2 .2h-.5l-.2-.2M157.4 84.5h.8l.2-.2v-.5l-.2-.3h-.8v1.5M165.3 91.3l.2-.2h1l.3 .2v.5l-.3 .2h-1l-.2-.2zM165.3 97.7v.5M165.3 98h1.5M165.5 89.4l-.2 .2v.5l.2 .2h1l.3-.2v-.5l-.3-.2h-.5v.5M166.3 93.7v-.7l-.3-.2h-.5l-.2 .2v.7h1.5M166.3 95.4v-.7l-.3-.3h-.5l-.2 .3v.7h1.5M166.3 99.9v-.7l-.3-.3h-.5l-.2 .3v.7h1.5M166.8 97.7v.5M166.8 92.8l-.5 .4M167 96.1v1"/>
<path d="M127.5 102.8h2.9l.5 .6v.5l-.5 .6M127.5 102.2v1.2M129.8 101v-1.7l-.6-.6h-1.1l-.6 .6v1.7h3.4M165.3 105.6h1l.5 .5-.5 .5h-1M165.5 100.6l-.2 .2v.5l.5 .3 .2-.3v-.5l.3-.2h.2l.3 .2v.5l-.3 .3M166 107.3v1M166.3 104.9v-.7l-.3-.2h-.5l-.2 .2v.7h1.5M166.8 107.3h-1l-.5 .5 .5 .5h1M166.8 104l-.5 .5M167 102.3v1M102.2 121.2h1.1l.6 .6v2.3l-.6 .6h-1.1l-.6-.6v-2.3zM107.4 121.8l-.6-.6h-1.1l-.6 .6v2.3l.6 .6h1.1l.6-.6"/>
<path d="M108.6 124.7h2.3M108.6 122.4l1.2-1.2v3.5M153.1 124.6l.3-.2h.9l.3 .2v.7h-1.5zM153.1 131.1v1M153.1 131.6h1.5M153.4 136.2l-.3 .2v.5l.3 .2 .4-.2v-.5l.3-.2h.2l.3 .2v.5l-.3 .2M153.4 127.7l-.3 .3v.5l.3 .2h.2l.2-.2v-.5l.3-.3h.2l.3 .3v.5l-.3 .2M153.4 132.8l-.3 .2v.5l.3 .3 .4-.3v-.5l.3-.2h.2l.3 .2v.5l-.3 .3M153.8 129.4v1M154.1 135.4v-.7l-.3-.2h-.4l-.3 .2v.7h1.5M154.6 126.1h-1.5l.5 .4-.5 .5h1.5M157.2 121.6h6.6"/>
<path d="M157.2 139.6h6.6M160.5 124.6v3l1.5 3.3M160.5 131.5v5.1M32 168.7l-.5-.6h-1.2l-.5 .6v2.3M32 168.7v2.3l-.5 .5h-1.2l-.5-.5M32 168.7l-2.2 2.3M33.3 162.5h1.8l.5-.5v-1.2l-.5-.5h-1.8v3.4M36.8 162.5h1.7l.6-.5v-1.2l-.6-.5h-1.7v3.4"/>
</g>
<g fill="none" stroke="#808080" stroke-width=".23">
<path d="M23.3 17.7l.7-.7v2.2M23.3 19.2h1.5M27 17.4v1.4l-.3 .4h-.8l-.4-.4M27 17.4l-.3-.4h-.8l-.4 .4v1.4M27 17.4l-1.5 1.4M29.3 17.4v1.4l-.4 .4h-.7l-.4-.4M29.3 17.4l-.4-.4h-.7l-.4 .4v1.4M29.3 17.4l-1.5 1.4M30.1 17.7v1.1l.3 .4h1.1v-1.5M32.3 18.1h.7M33.8 17h-1.5v2.2M130.9 36.6v3l.7 .6h1.1l.6-.6v-3"/>
<path d="M134.5 37.2l.5-.6h1.2l.6 .6v.6l-.6 .6M135.7 38.4h.5M136.2 38.4l.6 .6v.6l-.6 .6h-1.2l-.5-.6M119 47.9l2.4 2.3M119 49h2.4M120.2 47.9v2.3M121.4 47.9l-2.4 2.3"/>
</g>
<g fill="none" stroke="#808080" stroke-width=".32">
<path d="M13.3 46.9h1.1M13.8 46.9v2.9l-.5 .6h-.6l-.6-.6M15.6 50.4h2.3M15.6 48.1l1.1-1.2v3.5M46.1 53.8v25.5h-35.9M50.6 53.8v24M52.1 53.8v24h-31.5M151.8 58.4h2.3v.5l-2.3 2.4v.6M16.2 68.8h3M16.2 62.8h3M22.1 68.8h3M22.1 62.8h3"/>
<path d="M28.2 68.8h2.9M28.2 62.8h2.9M34.1 68.8h3M34.1 62.8h3M148.3 60.7h1.7l.6-.6v-1.2l-.6-.5h-1.7v3.5M149.4 60.7l1.2 1.2M154.5 71v2.3h1.8l-.6-1.2v-.6l.6-.5h1.1l.6 .5v1.2l-.6 .6M154.5 67.4l.6 1.2 1.2 1.2M155.1 63.9l-.6 .6v1.2l.6 .6h2.3M155.1 63.9h2.3l.6 .6v1.2l-.6 .6M155.1 63.9l2.3 2.4M156.3 68l.6-.6h.5l.6 .6v1.2l-.6 .6h-1.1z"/>
<path d="M14.2 94.4h2.3l1.2 1.2-1.2 1.2h-2.3M14.2 91.5l.6-.6h2.3l.6 .6v1.8h-3.5zM14.2 97.9v2.4h1.7l-.6-1.2v-.6l.6-.6h1.2l.6 .6v1.2l-.6 .6M14.8 87.4l-.6 .6v1.2l.6 .5h2.3l.6-.5v-1.2l-.6-.6M58 90.9v2.4h3.5v-2.4M59.7 92.1v1.2M60.3 96.8v-1.8l-.6-.6h-1.2l-.5 .6v1.8h3.5M61.5 94.4l-1.2 1.2M61.5 87.4v2.3M61.5 88.6h-3.5l1.1 1.1M14.8 104.9l-.6 .6v1.2l.6 .6h.5l.6-.6v-1.2l.6-.6h.6l.6 .6v1.2l-.6 .6M14.8 115.5l-.6 .6v1.1l.6 .6h.5l.6-.6v-1.1l.6-.6h.6l.6 .6v1.1l-.6 .6"/>
<path d="M15.9 108.5v2.3M17.7 112v2.3h-.6l-2.3-2.3h-.6v2.3M17.7 101.5v2.3h-3.5M17.7 119l-1.2 1.1M14.8 122.5l-.6 .6v1.1l.6 .6h.5l.6-.6v-1.1l.6-.6h.6l.6 .6v1.1l-.6 .6M16.5 121.3v-1.7l-.6-.6h-1.1l-.6 .6v1.7h3.5M138.5 122.5h3.5M138.5 120.2l2.4 2.3M140.3 124.3l.6-.6h.5l.6 .6v1.1l-.6 .6h-.5l-.6-.6M140.3 124.3l-.6-.6h-.6l-.6 .6v1.1l.6 .6h.6l.6-.6M140.3 124.3v1.1M142 128.4h-3.5l1.2 1.1"/>
<path d="M142 127.2v2.3M142 120.2l-1.7 1.7M144.6 159.7v.6l1.2 1.1M145.4 153.3h5.7M145.4 158.1h5.7M147 159.7v.6l-1.2 1.1M150.5 159.7h-2.4v3.5h2.4M151.6 159.7v3.5h2.4M155.2 159.7v3.5h2.3M162.2 159.7v3.5l1.1-1.2 1.2 1.2v-3.5M145.8 161.4v1.8M148.1 161.4h1.2"/>
<path d="M158.6 160.3l.6-.6h1.2l.6 .6v2.3l-.6 .6h-1.2l-.6-.6z"/>
<circle cx="152.5" cy="154.1" r=".3"/>
</g>
<path d="M29.9 32.7l-.2-.2h-.3l-.2 .2v.8l.2 .2h.3l.2-.2M30.3 33.7h.8M30.3 32.9l.4-.4v1.2M76.7 53.6h.5l.2 .2v.8l-.2 .2h-.5zM77.8 54.8h.7M77.8 54l.4-.4v1.2" fill="none" stroke="#808080" stroke-width=".21"/>
<path d="M65.2 93h1.6M65.2 88.2h1.6M66 88.2v4.8M71.6 89l-.8-.8h-1.6l-.8 .8v3.2l.8 .8h1.6l.8-.8M73.3 93h3.2M73.3 89.8l1.7-1.6v4.8M76.6 87.4h-3.2v2.4l1.6-.8h.8l.8 .8v1.6l-.8 .8h-1.6l-.8-.8M78.3 87.4v3.2l1.6 1.6 1.6-1.6v-3.2" fill="none" stroke="#808080" stroke-width=".55"/>
<g fill="none" stroke="#000" stroke-width=".21">
<path d="M19.4 15.6h150v150h-150zM27.2 27.9h3.1M28.7 26.4v3.1M47.5 27.7h3.5M49.3 26v3.5M108.3 38.4h3.8M110.2 36.5v3.8M130.7 38.4h6.1M133.8 35.3v6.1M55.3 44.6h3.8M57.2 42.7v3.8M83.4 58.6h1.7"/>
<path d="M84.2 57.8v1.7M161.2 53.6h3.1M162.8 52.1v3.1M39.3 65.8h6.1M42.4 62.8v6.1M68.1 79.5h6.1M71.1 76.5v6.1M121.7 71.9h2.9M123.1 70.5v2.9M149.3 69.6h2.5M150.6 68.3v2.6M125.6 82.5h2.5"/>
<path d="M126.9 81.2v2.5M134.6 97.1h2.9M136.1 95.6v2.9M34.8 109.3h6.1M37.8 106.2v6.1M103.6 113.8h4.1M105.6 111.8v4.1M157.6 104.7h4.2M159.7 102.6v4.1M144.4 123h3.1M146 121.4v3.1M159.1 130.6h2.7"/>
<path d="M160.5 129.2v2.8M41.6 148.9h6.1M44.7 145.8v6.1M147.1 155.7h2.4M148.3 154.5v2.5"/>
<circle cx="145.4" cy="138.6" r="3"/>
</g>
<circle cx="145.4" cy="138.6" r="3" fill="#fff" stroke="#000" stroke-width=".21"/>
<circle cx="43.4" cy="42.7" r="3" fill="none" stroke="#000" stroke-width=".21"/>
<circle cx="43.4" cy="42.7" r="3" fill="#fff" stroke="#000" stroke-width=".21"/>
<g fill="none" stroke="#000" stroke-width=".32">
<circle cx="43.4" cy="42.5" r="6"/>
<circle cx="145.6" cy="138.5" r="6"/>
</g>
<circle cx="71.1" cy="113.1" r="5" fill="none" stroke="#000" stroke-width=".21"/>
<circle cx="71.1" cy="113.1" r="5" fill="#fff" stroke="#000" stroke-width=".21"/>
<circle cx="71.1" cy="113.1" r="12.6" fill="#008000" stroke="#008000" stroke-width=".21"/>
<g fill="none" stroke="#808080" stroke-width=".21">
<path d="M21.8 24.9h6.1v6.1h-6.1zM24.9 24.9v3M29.5 24.9h6.1v6.1h-6.1zM32.5 24.9v3M44.7 24.7l-6.1 6.1M46.5 39.6v6.1l-3.1-3zM52.3 24.7l-6.1 6.1M59.9 24.7l-6.1 6.1M60.3 34l-6.1 6M84.2 28.5l-6.1 6.1M101.8 37.3l-6.1 6.1M101.8 28.1l-6.1 6.1"/>
<path d="M103.9 23.5l-6.1 6.1M113.2 27.7l-6.1 6.1M127.3 34l-6.1 6M140.7 28.9l-6.1 6.1M149.9 34.4l-6.1 6M165.8 39.2l-6.1 6.1M165.8 31.5l-6.1 6.1M40.4 42.7h3M60.3 49.2l-6.1 6.1M69.8 55.6h6.1l-6.1 6.1h6.1zM83.8 43.6l-6.1 6.1M85.4 59.5l-6.1 6.1"/>
<path d="M92.6 55.6h6.1l-6.1 6.1h6.1zM112.2 49.9l-6 6.1M113.2 43l-6.1 6.1M113.5 55.7l-6.1 6.1M124.4 54.9l-6.1 6.1M127.7 55.7l-6.1 6.1M150.4 44.4l-6.1 6.1M165.8 54.4l-6.1 6.1M165.8 46.8l-6.1 6.1M33.4 62.8v3M33.4 62.8l3 3-3 3.1-3-3.1zM42.4 77.2v3"/>
<path d="M42.4 77.2l3 3-3 3.1-3.1-3.1zM48.3 62.8l6.1 6.1v-6.1l-6.1 6.1zM66.5 65.1l-6 6.1M74.2 65.1l-6.1 6.1M81.8 65.1l-6.1 6.1M88.8 62.9l-6.1 6.1M91.7 69.1l-6.1 6.1M104.3 71.6l-6.1 6.1M107.1 68.9l-6.1 6.1M114.7 79.4l-6.1 6.1M145.2 79.4l-6.1 6.1M145.2 68.9l-6.1 6.1"/>
<path d="M155.4 75.4l-6.1 6.1M165.8 69.6l-6.1 6.1M165.8 62l-6.1 6.1M26.4 87.2v3M26.4 94.8v3M26.4 87.2l3 3-3 3.1-3.1-3.1zM26.4 94.8l3 3-3 3.1-3.1-3.1zM49.3 87.2v3M49.3 94.8v3M49.3 87.2l3 3-3 3.1-3.1-3.1zM49.3 94.8l3 3-3 3.1-3.1-3.1zM102.6 91.6h6.1l-6.1 6.1h6.1z"/>
<path d="M139.1 97.8l-6.1 6.1M139.1 90.2l-6.1 6.1M155.1 94l-6.1 6.1M155.1 86.4l-6.1 6.1M162.8 94l-6.1 6.1M162.8 86.4l-6.1 6.1M167.1 91.8l-6.1 6.1M74.2 110l-6.1 6.1M155.1 101.6l-6.1 6.1M162.8 101.6l-6.1 6.1M49.3 125.2v3.1M49.3 125.2l3 3.1-3 3-3.1-3z"/>
<path d="M142.3 138.6h3.1M148.4 135.6v6.1l-3-3.1zM40.2 149.6l-6.1 6.1M55.2 149.6l-6.1 6.1M102.6 151.6h6.1l-6.1 6.1h6.1z"/>
<circle cx="41.6" cy="27.7" r="2.96"/>
<circle cx="49.3" cy="27.7" r="2.96"/>
<circle cx="56.9" cy="27.7" r="2.96"/>
<circle cx="57.2" cy="37" r="2.96"/>
<circle cx="81.1" cy="31.5" r="2.96"/>
<circle cx="98.7" cy="31.1" r="2.96"/>
<circle cx="100.8" cy="26.5" r="2.96"/>
<circle cx="110.2" cy="30.8" r="2.96"/>
<circle cx="124.3" cy="37" r="2.96"/>
<circle cx="137.7" cy="32" r="2.96"/>
<circle cx="146.9" cy="37.4" r="2.96"/>
<circle cx="162.8" cy="34.6" r="2.96"/>
<circle cx="57.2" cy="52.2" r="2.96"/>
<circle cx="80.7" cy="46.6" r="2.96"/>
<circle cx="98.7" cy="40.3" r="2.96"/>
<circle cx="109.2" cy="52.9" r="2.96"/>
<circle cx="110.2" cy="46" r="2.96"/>
<circle cx="110.4" cy="58.8" r="2.96"/>
<circle cx="121.3" cy="57.9" r="2.96"/>
<circle cx="124.7" cy="58.8" r="2.96"/>
<circle cx="147.3" cy="47.5" r="2.96"/>
<circle cx="162.8" cy="49.8" r="2.96"/>
<circle cx="162.8" cy="57.4" r="2.96"/>
<circle cx="162.8" cy="42.2" r="2.96"/>
<circle cx="63.5" cy="68.1" r="2.96"/>
<circle cx="71.1" cy="68.1" r="2.96"/>
<circle cx="78.7" cy="68.1" r="2.96"/>
<circle cx="82.4" cy="62.5" r="2.96"/>
<circle cx="85.7" cy="65.9" r="2.96"/>
<circle cx="88.7" cy="72.2" r="2.96"/>
<circle cx="101.2" cy="74.7" r="2.96"/>
<circle cx="104.1" cy="71.9" r="2.96"/>
<circle cx="142.2" cy="71.9" r="2.96"/>
<circle cx="152.4" cy="78.5" r="2.96"/>
<circle cx="162.8" cy="72.7" r="2.96"/>
<circle cx="162.8" cy="65.1" r="2.96"/>
<circle cx="111.6" cy="82.5" r="2.96"/>
<circle cx="136.1" cy="93.3" r="2.96"/>
<circle cx="142.1" cy="82.5" r="2.96"/>
<circle cx="152.1" cy="97.1" r="2.96"/>
<circle cx="152.1" cy="89.5" r="2.96"/>
<circle cx="159.7" cy="97.1" r="2.96"/>
<circle cx="159.7" cy="89.5" r="2.96"/>
<circle cx="164.1" cy="94.8" r="2.96"/>
<circle cx="71.1" cy="113.1" r="2.96"/>
<circle cx="136.1" cy="100.9" r="2.96"/>
<circle cx="152.1" cy="104.7" r="2.96"/>
<circle cx="159.7" cy="104.7" r="2.96"/>
<circle cx="37.2" cy="152.7" r="2.96"/>
<circle cx="52.2" cy="152.7" r="2.96"/>
</g>
<g fill="none" stroke="#008080" stroke-width=".21">
<path d="M25.3 72l.3-.3h.6l.2 .3v.2l-.2 .3M25.9 72.5h.3M26.2 72.5l.2 .3v.3l-.2 .3h-.6l-.3-.3M29.8 72l-.3-.3h-.5l-.3 .3v.2l.3 .3h.5l.3 .3v.3l-.3 .3h-.5l-.3-.3M30.4 71.7h.2v1.7M30.4 73.4h.5M31.8 72.2h.5l.3 .3v.6l-.3 .3h-.5l-.3-.3v-.6zM32.2 61.3h2.4v9h-2.4zM33.2 72.2h.5M33.5 72v1.1l.2 .3M36 71.7h.8l.3 .3v1.1l-.3 .3h-.8zM37.7 72.2v1.2"/>
<path d="M37.9 79h9v2.4h-9zM38.5 72.2h-.3l-.5 .6M39.1 73.4h.5M39.1 72.2h.2v1.2M39.3 71.4v.3M40.2 71.7h.3v1.7M40.2 73.4h.5M41.3 71.7h.3v1.7M41.3 73.4h.6M43.6 72.2h-.9l-.3 .3 .3 .3h.6l.3 .3-.3 .3h-.9M45.8 72.2v.9l.3 .3 .3-.3 .3 .3 .2-.3v-.9M47.5 73.4h.5"/>
<path d="M47.5 72.2h.3v1.2M47.8 71.4v.3M48.6 72.2h.6M48.9 72v1.1l.3 .3M49.7 72.5l.3-.3h.6l.3 .3v.9M49.7 71.7v1.7M49.9 60.6h3v10.5h-3zM54.2 72.2h-.8l-.3 .3v.6l.3 .3h.8M54.8 72.5l.3-.3h.5l.3 .3v.6l-.3 .3h-.5l-.3-.3zM56.5 73.4h.8l.3-.3v-.6l-.3-.3h-.8v1.7M58.1 73.4h.9l.3-.3v-.6l-.3-.3h-.9v1.7M59.8 72.8h1.2v-.3l-.3-.3h-.6l-.3 .3v.6l.3 .3h.6"/>
<path d="M61.5 72.2v1.2M62.4 72.2h-.3l-.6 .6"/>
</g>
<g fill="#008080" stroke="#008080" stroke-width=".21">
<path d="M32.2 61.3h2.3v7h-2.3z"/>
<path d="M32.2 68.3h2.4v2h-2.4z"/>
<path d="M34.5 61.3h.1v7h-.1z"/>
<path d="M49.9 60.6h3v10.5h-3z"/>
<path d="M49.9 60.6h3z"/>
<path d="M49.9 60.6h.2v3.7h-.2z"/>
<path d="M49.8 60.6l.1 5.7z"/>
<path d="M49.8 66.3l.1 4.8z"/>
<path d="M37.9 79h9v2.4h-9z"/>
</g>
<path d="M37.1 65.8h11M37.1 65.8l1.5 .8M38.6 65.1l-1.5 .7M41.6 75.4l.8 1.5M42.4 65.8v5.7M42.4 73.8v3.1M43.2 75.4l-.8 1.5M46.6 65.1l1.5 .7M48.1 65.8l-1.5 .8" fill="none" stroke="#008080" stroke-width=".38"/>
</svg>
